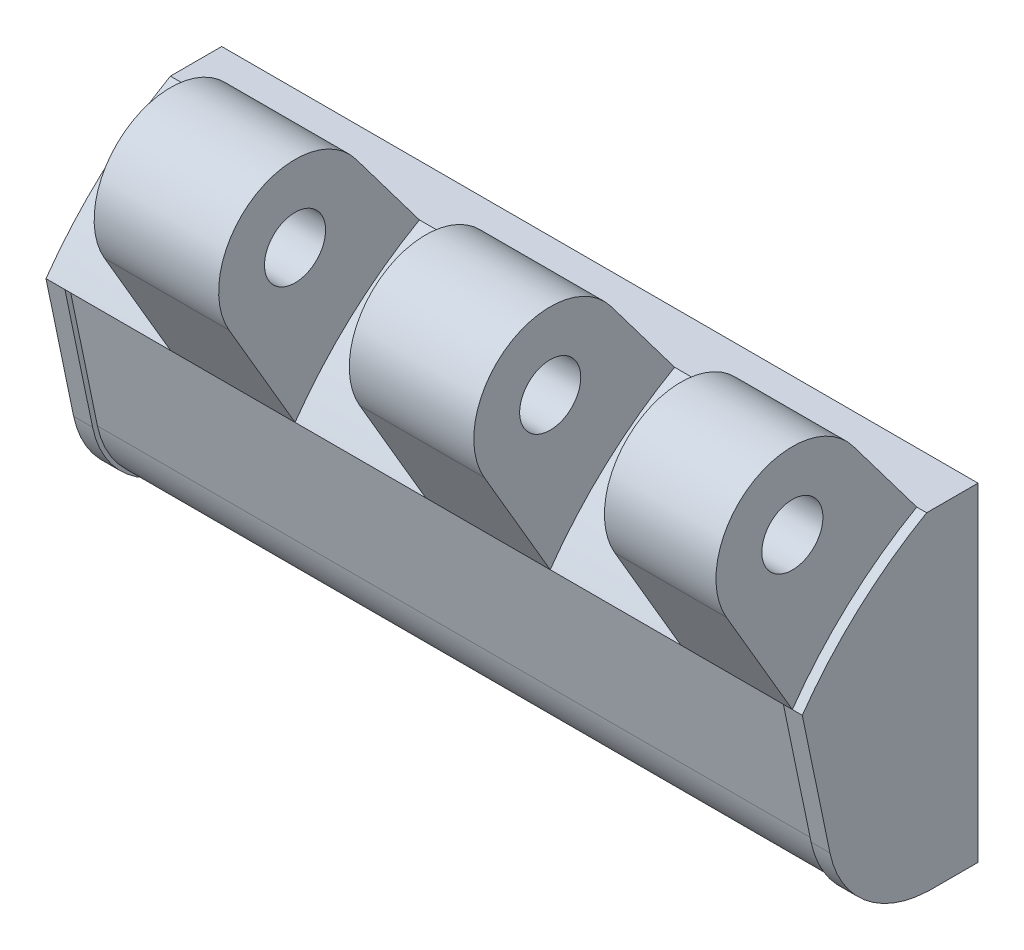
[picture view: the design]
ISO-10303-21;
HEADER;
FILE_DESCRIPTION(('STEP AP214'),'2;1');
FILE_NAME('part.step','',(''),(''),'','','');
FILE_SCHEMA(('AUTOMOTIVE_DESIGN { 1 0 10303 214 1 1 1 1 }'));
ENDSEC;
DATA;
#1=APPLICATION_CONTEXT('core data for automotive mechanical design processes');
#2=APPLICATION_PROTOCOL_DEFINITION('international standard','automotive_design',2000,#1);
#3=PRODUCT_CONTEXT('',#1,'mechanical');
#4=PRODUCT('Part','Part','',(#3));
#5=PRODUCT_RELATED_PRODUCT_CATEGORY('part','',(#4));
#6=PRODUCT_DEFINITION_FORMATION('','',#4);
#7=PRODUCT_DEFINITION_CONTEXT('part definition',#1,'design');
#8=PRODUCT_DEFINITION('design','',#6,#7);
#9=PRODUCT_DEFINITION_SHAPE('','',#8);
#10=(LENGTH_UNIT() NAMED_UNIT(*) SI_UNIT(.MILLI.,.METRE.));
#11=(NAMED_UNIT(*) PLANE_ANGLE_UNIT() SI_UNIT($,.RADIAN.));
#12=(NAMED_UNIT(*) SI_UNIT($,.STERADIAN.) SOLID_ANGLE_UNIT());
#13=UNCERTAINTY_MEASURE_WITH_UNIT(LENGTH_MEASURE(1.E-05),#10,'distance_accuracy_value','');
#14=(GEOMETRIC_REPRESENTATION_CONTEXT(3) GLOBAL_UNCERTAINTY_ASSIGNED_CONTEXT((#13)) GLOBAL_UNIT_ASSIGNED_CONTEXT((#10,
#11,#12)) REPRESENTATION_CONTEXT('',''));
#15=CARTESIAN_POINT('',(0.,0.,0.));
#16=DIRECTION('',(0.,0.,1.));
#17=DIRECTION('',(1.,0.,0.));
#18=AXIS2_PLACEMENT_3D('',#15,#16,#17);
#19=CARTESIAN_POINT('',(38.63875,-1.75,3.09));
#20=DIRECTION('',(1.,0.,0.));
#21=DIRECTION('',(0.,1.,0.));
#22=AXIS2_PLACEMENT_3D('',#19,#20,#21);
#23=CYLINDRICAL_SURFACE('',#22,5.54);
#24=DIRECTION('',(1.,0.,0.));
#25=VECTOR('',#24,1.);
#26=CARTESIAN_POINT('',(2.8867513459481,-5.,7.57654655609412));
#27=LINE('',#26,#25);
#28=CARTESIAN_POINT('',(2.8867513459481,-5.,7.57654655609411));
#29=VERTEX_POINT('',#28);
#30=CARTESIAN_POINT('',(-2.8867513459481,-5.,7.57654655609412));
#31=VERTEX_POINT('',#30);
#32=EDGE_CURVE('E448',#29,#31,#27,.F.);
#33=ORIENTED_EDGE('',*,*,#32,.T.);
#34=CARTESIAN_POINT('',(-4.7631397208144,-1.75,3.09));
#35=DIRECTION('',(-0.866025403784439,-0.5,0.));
#36=DIRECTION('',(0.5,-0.866025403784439,0.));
#37=AXIS2_PLACEMENT_3D('',#34,#35,#36);
#38=ELLIPSE('',#37,6.39704098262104,5.54);
#39=CARTESIAN_POINT('',(-4.11231595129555,-2.8772598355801,8.51410225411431));
#40=VERTEX_POINT('',#39);
#41=EDGE_CURVE('E386',#31,#40,#38,.T.);
#42=ORIENTED_EDGE('',*,*,#41,.T.);
#43=DIRECTION('',(1.,0.,0.));
#44=VECTOR('',#43,1.);
#45=CARTESIAN_POINT('',(38.63875,-2.8772598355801,8.51410225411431));
#46=LINE('',#45,#44);
#47=CARTESIAN_POINT('',(4.11231595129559,-2.8772598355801,8.51410225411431));
#48=VERTEX_POINT('',#47);
#49=EDGE_CURVE('E376',#48,#40,#46,.F.);
#50=ORIENTED_EDGE('',*,*,#49,.F.);
#51=CARTESIAN_POINT('',(4.7631397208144,-1.75,3.09));
#52=DIRECTION('',(0.866025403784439,-0.5,0.));
#53=DIRECTION('',(0.5,0.866025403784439,0.));
#54=AXIS2_PLACEMENT_3D('',#51,#52,#53);
#55=ELLIPSE('',#54,6.39704098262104,5.54);
#56=EDGE_CURVE('E450',#48,#29,#55,.T.);
#57=ORIENTED_EDGE('',*,*,#56,.T.);
#58=EDGE_LOOP('',(#33,#42,#50,#57));
#59=FACE_BOUND('',#58,.T.);
#60=ADVANCED_FACE('F14',(#59),#23,.F.);
#61=CARTESIAN_POINT('',(38.63875,-2.8772598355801,8.51410225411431));
#62=DIRECTION('',(0.,0.203476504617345,-0.979079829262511));
#63=DIRECTION('',(0.,0.979079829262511,0.203476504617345));
#64=AXIS2_PLACEMENT_3D('',#61,#62,#63);
#65=PLANE('',#64);
#66=DIRECTION('',(-1.,0.,0.));
#67=VECTOR('',#66,1.);
#68=CARTESIAN_POINT('',(-2.8867513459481,5.,10.151187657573));
#69=LINE('',#68,#67);
#70=CARTESIAN_POINT('',(-2.88675134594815,5.,10.151187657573));
#71=VERTEX_POINT('',#70);
#72=CARTESIAN_POINT('',(2.8867513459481,5.,10.151187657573));
#73=VERTEX_POINT('',#72);
#74=EDGE_CURVE('E476',#71,#73,#69,.F.);
#75=ORIENTED_EDGE('',*,*,#74,.T.);
#76=DIRECTION('',(0.492093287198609,-0.852330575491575,-0.177134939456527));
#77=VECTOR('',#76,1.);
#78=CARTESIAN_POINT('',(2.8867513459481,5.,10.151187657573));
#79=LINE('',#78,#77);
#80=CARTESIAN_POINT('',(5.77350269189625,0.,9.11206654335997));
#81=VERTEX_POINT('',#80);
#82=EDGE_CURVE('E495',#73,#81,#79,.T.);
#83=ORIENTED_EDGE('',*,*,#82,.T.);
#84=DIRECTION('',(-0.49209328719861,-0.852330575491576,-0.177134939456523));
#85=VECTOR('',#84,1.);
#86=CARTESIAN_POINT('',(5.77350269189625,0.,9.11206654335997));
#87=LINE('',#86,#85);
#88=EDGE_CURVE('E508',#81,#48,#87,.T.);
#89=ORIENTED_EDGE('',*,*,#88,.T.);
#90=ORIENTED_EDGE('',*,*,#49,.T.);
#91=DIRECTION('',(-0.49209328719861,0.852330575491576,0.177134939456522));
#92=VECTOR('',#91,1.);
#93=CARTESIAN_POINT('',(-4.11231595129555,-2.87725983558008,8.51410225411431));
#94=LINE('',#93,#92);
#95=CARTESIAN_POINT('',(-5.77350269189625,0.,9.11206654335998));
#96=VERTEX_POINT('',#95);
#97=EDGE_CURVE('E466',#40,#96,#94,.T.);
#98=ORIENTED_EDGE('',*,*,#97,.T.);
#99=DIRECTION('',(0.492093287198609,0.852330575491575,0.177134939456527));
#100=VECTOR('',#99,1.);
#101=CARTESIAN_POINT('',(-5.7735026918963,0.,9.11206654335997));
#102=LINE('',#101,#100);
#103=EDGE_CURVE('E463',#96,#71,#102,.T.);
#104=ORIENTED_EDGE('',*,*,#103,.T.);
#105=EDGE_LOOP('',(#75,#83,#89,#90,#98,#104));
#106=FACE_BOUND('',#105,.T.);
#107=ADVANCED_FACE('F16',(#106),#65,.T.);
#108=CARTESIAN_POINT('',(38.63875,-1.75,3.09));
#109=DIRECTION('',(1.,0.,0.));
#110=DIRECTION('',(0.,1.,0.));
#111=AXIS2_PLACEMENT_3D('',#108,#109,#110);
#112=CYLINDRICAL_SURFACE('',#111,5.54);
#113=DIRECTION('',(1.,0.,0.));
#114=VECTOR('',#113,1.);
#115=CARTESIAN_POINT('',(38.63875,-2.8772598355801,8.51410225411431));
#116=LINE('',#115,#114);
#117=CARTESIAN_POINT('',(34.6123159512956,-2.8772598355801,8.51410225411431));
#118=VERTEX_POINT('',#117);
#119=CARTESIAN_POINT('',(26.3876840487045,-2.8772598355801,8.51410225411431));
#120=VERTEX_POINT('',#119);
#121=EDGE_CURVE('E373',#118,#120,#116,.F.);
#122=ORIENTED_EDGE('',*,*,#121,.F.);
#123=CARTESIAN_POINT('',(35.2631397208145,-1.75,3.09));
#124=DIRECTION('',(0.866025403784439,-0.5,0.));
#125=DIRECTION('',(0.5,0.866025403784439,0.));
#126=AXIS2_PLACEMENT_3D('',#123,#124,#125);
#127=ELLIPSE('',#126,6.39704098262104,5.54);
#128=CARTESIAN_POINT('',(33.3867513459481,-5.,7.57654655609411));
#129=VERTEX_POINT('',#128);
#130=EDGE_CURVE('E385',#118,#129,#127,.T.);
#131=ORIENTED_EDGE('',*,*,#130,.T.);
#132=DIRECTION('',(1.,0.,0.));
#133=VECTOR('',#132,1.);
#134=CARTESIAN_POINT('',(33.3867513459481,-5.,7.57654655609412));
#135=LINE('',#134,#133);
#136=CARTESIAN_POINT('',(27.6132486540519,-5.,7.57654655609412));
#137=VERTEX_POINT('',#136);
#138=EDGE_CURVE('E383',#129,#137,#135,.F.);
#139=ORIENTED_EDGE('',*,*,#138,.T.);
#140=CARTESIAN_POINT('',(25.7368602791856,-1.75,3.09));
#141=DIRECTION('',(-0.866025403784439,-0.5,0.));
#142=DIRECTION('',(0.5,-0.866025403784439,0.));
#143=AXIS2_PLACEMENT_3D('',#140,#141,#142);
#144=ELLIPSE('',#143,6.39704098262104,5.54);
#145=EDGE_CURVE('E620',#137,#120,#144,.T.);
#146=ORIENTED_EDGE('',*,*,#145,.T.);
#147=EDGE_LOOP('',(#122,#131,#139,#146));
#148=FACE_BOUND('',#147,.T.);
#149=ADVANCED_FACE('F924',(#148),#112,.F.);
#150=CARTESIAN_POINT('',(38.63875,-2.8772598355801,8.51410225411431));
#151=DIRECTION('',(0.,0.203476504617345,-0.979079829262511));
#152=DIRECTION('',(0.,0.979079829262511,0.203476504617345));
#153=AXIS2_PLACEMENT_3D('',#150,#151,#152);
#154=PLANE('',#153);
#155=DIRECTION('',(-0.49209328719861,-0.852330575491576,-0.177134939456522));
#156=VECTOR('',#155,1.);
#157=CARTESIAN_POINT('',(36.2735026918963,0.,9.11206654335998));
#158=LINE('',#157,#156);
#159=CARTESIAN_POINT('',(36.2735026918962,0.,9.11206654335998));
#160=VERTEX_POINT('',#159);
#161=EDGE_CURVE('E439',#160,#118,#158,.T.);
#162=ORIENTED_EDGE('',*,*,#161,.T.);
#163=ORIENTED_EDGE('',*,*,#121,.T.);
#164=DIRECTION('',(-0.49209328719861,0.852330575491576,0.177134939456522));
#165=VECTOR('',#164,1.);
#166=CARTESIAN_POINT('',(26.3876840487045,-2.87725983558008,8.51410225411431));
#167=LINE('',#166,#165);
#168=CARTESIAN_POINT('',(24.7264973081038,0.,9.11206654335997));
#169=VERTEX_POINT('',#168);
#170=EDGE_CURVE('E622',#120,#169,#167,.T.);
#171=ORIENTED_EDGE('',*,*,#170,.T.);
#172=DIRECTION('',(0.492093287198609,0.852330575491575,0.177134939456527));
#173=VECTOR('',#172,1.);
#174=CARTESIAN_POINT('',(24.7264973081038,0.,9.11206654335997));
#175=LINE('',#174,#173);
#176=CARTESIAN_POINT('',(27.6132486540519,5.,10.151187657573));
#177=VERTEX_POINT('',#176);
#178=EDGE_CURVE('E380',#169,#177,#175,.T.);
#179=ORIENTED_EDGE('',*,*,#178,.T.);
#180=DIRECTION('',(-1.,0.,0.));
#181=VECTOR('',#180,1.);
#182=CARTESIAN_POINT('',(27.6132486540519,5.,10.151187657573));
#183=LINE('',#182,#181);
#184=CARTESIAN_POINT('',(33.3867513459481,5.,10.151187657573));
#185=VERTEX_POINT('',#184);
#186=EDGE_CURVE('E412',#177,#185,#183,.F.);
#187=ORIENTED_EDGE('',*,*,#186,.T.);
#188=DIRECTION('',(0.492093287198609,-0.852330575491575,-0.177134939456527));
#189=VECTOR('',#188,1.);
#190=CARTESIAN_POINT('',(33.3867513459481,5.,10.151187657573));
#191=LINE('',#190,#189);
#192=EDGE_CURVE('E426',#185,#160,#191,.T.);
#193=ORIENTED_EDGE('',*,*,#192,.T.);
#194=EDGE_LOOP('',(#162,#163,#171,#179,#187,#193));
#195=FACE_BOUND('',#194,.T.);
#196=ADVANCED_FACE('F748',(#195),#154,.T.);
#197=CARTESIAN_POINT('',(-2.8867513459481,5.,2.2));
#198=DIRECTION('',(0.,1.,0.));
#199=DIRECTION('',(-1.,0.,0.));
#200=AXIS2_PLACEMENT_3D('',#197,#198,#199);
#201=PLANE('',#200);
#202=DIRECTION('',(0.,0.,1.));
#203=VECTOR('',#202,1.);
#204=CARTESIAN_POINT('',(-2.88675134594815,5.,2.2));
#205=LINE('',#204,#203);
#206=CARTESIAN_POINT('',(-2.88675134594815,5.,2.2));
#207=VERTEX_POINT('',#206);
#208=EDGE_CURVE('E467',#71,#207,#205,.F.);
#209=ORIENTED_EDGE('',*,*,#208,.T.);
#210=DIRECTION('',(1.,0.,0.));
#211=VECTOR('',#210,1.);
#212=CARTESIAN_POINT('',(15.25,5.,2.2));
#213=LINE('',#212,#211);
#214=CARTESIAN_POINT('',(2.8867513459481,5.,2.2));
#215=VERTEX_POINT('',#214);
#216=EDGE_CURVE('E486',#215,#207,#213,.F.);
#217=ORIENTED_EDGE('',*,*,#216,.F.);
#218=DIRECTION('',(0.,0.,1.));
#219=VECTOR('',#218,1.);
#220=CARTESIAN_POINT('',(2.8867513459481,5.,2.2));
#221=LINE('',#220,#219);
#222=EDGE_CURVE('E481',#73,#215,#221,.F.);
#223=ORIENTED_EDGE('',*,*,#222,.F.);
#224=ORIENTED_EDGE('',*,*,#74,.F.);
#225=EDGE_LOOP('',(#209,#217,#223,#224));
#226=FACE_BOUND('',#225,.T.);
#227=ADVANCED_FACE('F726',(#226),#201,.F.);
#228=CARTESIAN_POINT('',(2.8867513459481,5.,2.2));
#229=DIRECTION('',(0.866025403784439,0.5,0.));
#230=DIRECTION('',(-0.5,0.866025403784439,0.));
#231=AXIS2_PLACEMENT_3D('',#228,#229,#230);
#232=PLANE('',#231);
#233=ORIENTED_EDGE('',*,*,#222,.T.);
#234=DIRECTION('',(-0.5,0.866025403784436,0.));
#235=VECTOR('',#234,1.);
#236=CARTESIAN_POINT('',(5.77350269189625,0.,2.2));
#237=LINE('',#236,#235);
#238=CARTESIAN_POINT('',(5.77350269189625,0.,2.2));
#239=VERTEX_POINT('',#238);
#240=EDGE_CURVE('E491',#239,#215,#237,.T.);
#241=ORIENTED_EDGE('',*,*,#240,.F.);
#242=DIRECTION('',(0.,0.,1.));
#243=VECTOR('',#242,1.);
#244=CARTESIAN_POINT('',(5.77350269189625,0.,2.2));
#245=LINE('',#244,#243);
#246=EDGE_CURVE('E500',#81,#239,#245,.F.);
#247=ORIENTED_EDGE('',*,*,#246,.F.);
#248=ORIENTED_EDGE('',*,*,#82,.F.);
#249=EDGE_LOOP('',(#233,#241,#247,#248));
#250=FACE_BOUND('',#249,.T.);
#251=ADVANCED_FACE('F723',(#250),#232,.F.);
#252=CARTESIAN_POINT('',(5.77350269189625,0.,2.2));
#253=DIRECTION('',(0.866025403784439,-0.5,0.));
#254=DIRECTION('',(0.5,0.866025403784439,0.));
#255=AXIS2_PLACEMENT_3D('',#252,#253,#254);
#256=PLANE('',#255);
#257=ORIENTED_EDGE('',*,*,#246,.T.);
#258=DIRECTION('',(0.5,0.866025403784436,0.));
#259=VECTOR('',#258,1.);
#260=CARTESIAN_POINT('',(2.8867513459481,-5.,2.2));
#261=LINE('',#260,#259);
#262=CARTESIAN_POINT('',(2.8867513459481,-5.,2.2));
#263=VERTEX_POINT('',#262);
#264=EDGE_CURVE('E454',#263,#239,#261,.T.);
#265=ORIENTED_EDGE('',*,*,#264,.F.);
#266=DIRECTION('',(0.,0.,1.));
#267=VECTOR('',#266,1.);
#268=CARTESIAN_POINT('',(2.8867513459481,-5.,2.2));
#269=LINE('',#268,#267);
#270=EDGE_CURVE('E627',#29,#263,#269,.F.);
#271=ORIENTED_EDGE('',*,*,#270,.F.);
#272=ORIENTED_EDGE('',*,*,#56,.F.);
#273=ORIENTED_EDGE('',*,*,#88,.F.);
#274=EDGE_LOOP('',(#257,#265,#271,#272,#273));
#275=FACE_BOUND('',#274,.T.);
#276=ADVANCED_FACE('F706',(#275),#256,.F.);
#277=CARTESIAN_POINT('',(2.8867513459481,-5.,2.2));
#278=DIRECTION('',(0.,-1.,0.));
#279=DIRECTION('',(1.,0.,0.));
#280=AXIS2_PLACEMENT_3D('',#277,#278,#279);
#281=PLANE('',#280);
#282=ORIENTED_EDGE('',*,*,#270,.T.);
#283=DIRECTION('',(1.,0.,0.));
#284=VECTOR('',#283,1.);
#285=CARTESIAN_POINT('',(15.25,-5.,2.2));
#286=LINE('',#285,#284);
#287=CARTESIAN_POINT('',(-2.8867513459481,-5.,2.2));
#288=VERTEX_POINT('',#287);
#289=EDGE_CURVE('E451',#288,#263,#286,.T.);
#290=ORIENTED_EDGE('',*,*,#289,.F.);
#291=DIRECTION('',(0.,0.,1.));
#292=VECTOR('',#291,1.);
#293=CARTESIAN_POINT('',(-2.8867513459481,-5.,2.2));
#294=LINE('',#293,#292);
#295=EDGE_CURVE('E472',#288,#31,#294,.T.);
#296=ORIENTED_EDGE('',*,*,#295,.T.);
#297=ORIENTED_EDGE('',*,*,#32,.F.);
#298=EDGE_LOOP('',(#282,#290,#296,#297));
#299=FACE_BOUND('',#298,.T.);
#300=ADVANCED_FACE('F702',(#299),#281,.F.);
#301=CARTESIAN_POINT('',(-2.8867513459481,-5.,2.2));
#302=DIRECTION('',(-0.866025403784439,-0.5,0.));
#303=DIRECTION('',(0.5,-0.866025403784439,0.));
#304=AXIS2_PLACEMENT_3D('',#301,#302,#303);
#305=PLANE('',#304);
#306=ORIENTED_EDGE('',*,*,#295,.F.);
#307=DIRECTION('',(0.500000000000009,-0.866025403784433,0.));
#308=VECTOR('',#307,1.);
#309=CARTESIAN_POINT('',(-5.7735026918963,0.,2.2));
#310=LINE('',#309,#308);
#311=CARTESIAN_POINT('',(-5.7735026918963,0.,2.2));
#312=VERTEX_POINT('',#311);
#313=EDGE_CURVE('E391',#312,#288,#310,.T.);
#314=ORIENTED_EDGE('',*,*,#313,.F.);
#315=DIRECTION('',(0.,0.,1.));
#316=VECTOR('',#315,1.);
#317=CARTESIAN_POINT('',(-5.77350269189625,0.,2.2));
#318=LINE('',#317,#316);
#319=EDGE_CURVE('E470',#96,#312,#318,.F.);
#320=ORIENTED_EDGE('',*,*,#319,.F.);
#321=ORIENTED_EDGE('',*,*,#97,.F.);
#322=ORIENTED_EDGE('',*,*,#41,.F.);
#323=EDGE_LOOP('',(#306,#314,#320,#321,#322));
#324=FACE_BOUND('',#323,.T.);
#325=ADVANCED_FACE('F716',(#324),#305,.F.);
#326=CARTESIAN_POINT('',(-5.7735026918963,0.,2.2));
#327=DIRECTION('',(-0.866025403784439,0.5,0.));
#328=DIRECTION('',(-0.5,-0.866025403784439,0.));
#329=AXIS2_PLACEMENT_3D('',#326,#327,#328);
#330=PLANE('',#329);
#331=ORIENTED_EDGE('',*,*,#319,.T.);
#332=DIRECTION('',(-0.500000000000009,-0.866025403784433,0.));
#333=VECTOR('',#332,1.);
#334=CARTESIAN_POINT('',(-2.8867513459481,5.,2.2));
#335=LINE('',#334,#333);
#336=EDGE_CURVE('E460',#207,#312,#335,.T.);
#337=ORIENTED_EDGE('',*,*,#336,.F.);
#338=ORIENTED_EDGE('',*,*,#208,.F.);
#339=ORIENTED_EDGE('',*,*,#103,.F.);
#340=EDGE_LOOP('',(#331,#337,#338,#339));
#341=FACE_BOUND('',#340,.T.);
#342=ADVANCED_FACE('F730',(#341),#330,.F.);
#343=CARTESIAN_POINT('',(27.6132486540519,5.,2.2));
#344=DIRECTION('',(0.,1.,0.));
#345=DIRECTION('',(-1.,0.,0.));
#346=AXIS2_PLACEMENT_3D('',#343,#344,#345);
#347=PLANE('',#346);
#348=DIRECTION('',(0.,0.,1.));
#349=VECTOR('',#348,1.);
#350=CARTESIAN_POINT('',(27.6132486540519,5.,2.2));
#351=LINE('',#350,#349);
#352=CARTESIAN_POINT('',(27.6132486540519,5.,2.2));
#353=VERTEX_POINT('',#352);
#354=EDGE_CURVE('E403',#177,#353,#351,.F.);
#355=ORIENTED_EDGE('',*,*,#354,.T.);
#356=DIRECTION('',(1.,0.,0.));
#357=VECTOR('',#356,1.);
#358=CARTESIAN_POINT('',(15.25,5.,2.2));
#359=LINE('',#358,#357);
#360=CARTESIAN_POINT('',(33.3867513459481,5.,2.2));
#361=VERTEX_POINT('',#360);
#362=EDGE_CURVE('E408',#361,#353,#359,.F.);
#363=ORIENTED_EDGE('',*,*,#362,.F.);
#364=DIRECTION('',(0.,0.,1.));
#365=VECTOR('',#364,1.);
#366=CARTESIAN_POINT('',(33.3867513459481,5.,2.2));
#367=LINE('',#366,#365);
#368=EDGE_CURVE('E417',#185,#361,#367,.F.);
#369=ORIENTED_EDGE('',*,*,#368,.F.);
#370=ORIENTED_EDGE('',*,*,#186,.F.);
#371=EDGE_LOOP('',(#355,#363,#369,#370));
#372=FACE_BOUND('',#371,.T.);
#373=ADVANCED_FACE('F732',(#372),#347,.F.);
#374=CARTESIAN_POINT('',(33.3867513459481,5.,2.2));
#375=DIRECTION('',(0.866025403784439,0.5,0.));
#376=DIRECTION('',(-0.5,0.866025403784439,0.));
#377=AXIS2_PLACEMENT_3D('',#374,#375,#376);
#378=PLANE('',#377);
#379=ORIENTED_EDGE('',*,*,#368,.T.);
#380=DIRECTION('',(-0.500000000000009,0.866025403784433,0.));
#381=VECTOR('',#380,1.);
#382=CARTESIAN_POINT('',(36.2735026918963,0.,2.2));
#383=LINE('',#382,#381);
#384=CARTESIAN_POINT('',(36.2735026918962,0.,2.2));
#385=VERTEX_POINT('',#384);
#386=EDGE_CURVE('E422',#385,#361,#383,.T.);
#387=ORIENTED_EDGE('',*,*,#386,.F.);
#388=DIRECTION('',(0.,0.,1.));
#389=VECTOR('',#388,1.);
#390=CARTESIAN_POINT('',(36.2735026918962,0.,2.2));
#391=LINE('',#390,#389);
#392=EDGE_CURVE('E431',#160,#385,#391,.F.);
#393=ORIENTED_EDGE('',*,*,#392,.F.);
#394=ORIENTED_EDGE('',*,*,#192,.F.);
#395=EDGE_LOOP('',(#379,#387,#393,#394));
#396=FACE_BOUND('',#395,.T.);
#397=ADVANCED_FACE('F740',(#396),#378,.F.);
#398=CARTESIAN_POINT('',(36.2735026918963,0.,2.2));
#399=DIRECTION('',(0.866025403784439,-0.5,0.));
#400=DIRECTION('',(0.5,0.866025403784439,0.));
#401=AXIS2_PLACEMENT_3D('',#398,#399,#400);
#402=PLANE('',#401);
#403=ORIENTED_EDGE('',*,*,#392,.T.);
#404=DIRECTION('',(0.500000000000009,0.866025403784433,0.));
#405=VECTOR('',#404,1.);
#406=CARTESIAN_POINT('',(33.3867513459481,-5.,2.2));
#407=LINE('',#406,#405);
#408=CARTESIAN_POINT('',(33.3867513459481,-5.,2.2));
#409=VERTEX_POINT('',#408);
#410=EDGE_CURVE('E390',#409,#385,#407,.T.);
#411=ORIENTED_EDGE('',*,*,#410,.F.);
#412=DIRECTION('',(0.,0.,1.));
#413=VECTOR('',#412,1.);
#414=CARTESIAN_POINT('',(33.3867513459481,-5.,2.2));
#415=LINE('',#414,#413);
#416=EDGE_CURVE('E624',#129,#409,#415,.F.);
#417=ORIENTED_EDGE('',*,*,#416,.F.);
#418=ORIENTED_EDGE('',*,*,#130,.F.);
#419=ORIENTED_EDGE('',*,*,#161,.F.);
#420=EDGE_LOOP('',(#403,#411,#417,#418,#419));
#421=FACE_BOUND('',#420,.T.);
#422=ADVANCED_FACE('F900',(#421),#402,.F.);
#423=CARTESIAN_POINT('',(33.3867513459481,-5.,2.2));
#424=DIRECTION('',(0.,-1.,0.));
#425=DIRECTION('',(1.,0.,0.));
#426=AXIS2_PLACEMENT_3D('',#423,#424,#425);
#427=PLANE('',#426);
#428=ORIENTED_EDGE('',*,*,#416,.T.);
#429=DIRECTION('',(1.,0.,0.));
#430=VECTOR('',#429,1.);
#431=CARTESIAN_POINT('',(15.25,-5.,2.2));
#432=LINE('',#431,#430);
#433=CARTESIAN_POINT('',(27.6132486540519,-5.,2.2));
#434=VERTEX_POINT('',#433);
#435=EDGE_CURVE('E387',#434,#409,#432,.T.);
#436=ORIENTED_EDGE('',*,*,#435,.F.);
#437=DIRECTION('',(0.,0.,1.));
#438=VECTOR('',#437,1.);
#439=CARTESIAN_POINT('',(27.6132486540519,-5.,2.2));
#440=LINE('',#439,#438);
#441=EDGE_CURVE('E379',#434,#137,#440,.T.);
#442=ORIENTED_EDGE('',*,*,#441,.T.);
#443=ORIENTED_EDGE('',*,*,#138,.F.);
#444=EDGE_LOOP('',(#428,#436,#442,#443));
#445=FACE_BOUND('',#444,.T.);
#446=ADVANCED_FACE('F745',(#445),#427,.F.);
#447=CARTESIAN_POINT('',(27.6132486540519,-5.,2.2));
#448=DIRECTION('',(-0.866025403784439,-0.5,0.));
#449=DIRECTION('',(0.5,-0.866025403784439,0.));
#450=AXIS2_PLACEMENT_3D('',#447,#448,#449);
#451=PLANE('',#450);
#452=ORIENTED_EDGE('',*,*,#145,.F.);
#453=ORIENTED_EDGE('',*,*,#441,.F.);
#454=DIRECTION('',(0.5,-0.866025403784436,0.));
#455=VECTOR('',#454,1.);
#456=CARTESIAN_POINT('',(24.7264973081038,0.,2.2));
#457=LINE('',#456,#455);
#458=CARTESIAN_POINT('',(24.7264973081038,0.,2.2));
#459=VERTEX_POINT('',#458);
#460=EDGE_CURVE('E394',#459,#434,#457,.T.);
#461=ORIENTED_EDGE('',*,*,#460,.F.);
#462=DIRECTION('',(0.,0.,1.));
#463=VECTOR('',#462,1.);
#464=CARTESIAN_POINT('',(24.7264973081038,0.,2.2));
#465=LINE('',#464,#463);
#466=EDGE_CURVE('E377',#169,#459,#465,.F.);
#467=ORIENTED_EDGE('',*,*,#466,.F.);
#468=ORIENTED_EDGE('',*,*,#170,.F.);
#469=EDGE_LOOP('',(#452,#453,#461,#467,#468));
#470=FACE_BOUND('',#469,.T.);
#471=ADVANCED_FACE('F891',(#470),#451,.F.);
#472=CARTESIAN_POINT('',(24.7264973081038,0.,2.2));
#473=DIRECTION('',(-0.866025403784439,0.5,0.));
#474=DIRECTION('',(-0.5,-0.866025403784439,0.));
#475=AXIS2_PLACEMENT_3D('',#472,#473,#474);
#476=PLANE('',#475);
#477=ORIENTED_EDGE('',*,*,#466,.T.);
#478=DIRECTION('',(-0.5,-0.866025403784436,0.));
#479=VECTOR('',#478,1.);
#480=CARTESIAN_POINT('',(27.6132486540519,5.,2.2));
#481=LINE('',#480,#479);
#482=EDGE_CURVE('E398',#353,#459,#481,.T.);
#483=ORIENTED_EDGE('',*,*,#482,.F.);
#484=ORIENTED_EDGE('',*,*,#354,.F.);
#485=ORIENTED_EDGE('',*,*,#178,.F.);
#486=EDGE_LOOP('',(#477,#483,#484,#485));
#487=FACE_BOUND('',#486,.T.);
#488=ADVANCED_FACE('F743',(#487),#476,.F.);
#489=CARTESIAN_POINT('',(15.25,15.5,2.2));
#490=DIRECTION('',(0.,0.,1.));
#491=DIRECTION('',(1.,0.,0.));
#492=AXIS2_PLACEMENT_3D('',#489,#490,#491);
#493=PLANE('',#492);
#494=ORIENTED_EDGE('',*,*,#336,.T.);
#495=ORIENTED_EDGE('',*,*,#313,.T.);
#496=ORIENTED_EDGE('',*,*,#289,.T.);
#497=ORIENTED_EDGE('',*,*,#264,.T.);
#498=ORIENTED_EDGE('',*,*,#240,.T.);
#499=ORIENTED_EDGE('',*,*,#216,.T.);
#500=EDGE_LOOP('',(#494,#495,#496,#497,#498,#499));
#501=FACE_BOUND('',#500,.T.);
#502=CARTESIAN_POINT('',(0.,0.,2.2));
#503=DIRECTION('',(0.,0.,1.));
#504=DIRECTION('',(1.,0.,0.));
#505=AXIS2_PLACEMENT_3D('',#502,#503,#504);
#506=CIRCLE('',#505,3.25);
#507=CARTESIAN_POINT('',(3.25,0.,2.2));
#508=VERTEX_POINT('',#507);
#509=EDGE_CURVE('E550',#508,#508,#506,.F.);
#510=ORIENTED_EDGE('',*,*,#509,.T.);
#511=EDGE_LOOP('',(#510));
#512=FACE_BOUND('',#511,.T.);
#513=ADVANCED_FACE('F710',(#501,#512),#493,.T.);
#514=CARTESIAN_POINT('',(15.25,15.5,2.2));
#515=DIRECTION('',(0.,0.,1.));
#516=DIRECTION('',(1.,0.,0.));
#517=AXIS2_PLACEMENT_3D('',#514,#515,#516);
#518=PLANE('',#517);
#519=ORIENTED_EDGE('',*,*,#482,.T.);
#520=ORIENTED_EDGE('',*,*,#460,.T.);
#521=ORIENTED_EDGE('',*,*,#435,.T.);
#522=ORIENTED_EDGE('',*,*,#410,.T.);
#523=ORIENTED_EDGE('',*,*,#386,.T.);
#524=ORIENTED_EDGE('',*,*,#362,.T.);
#525=EDGE_LOOP('',(#519,#520,#521,#522,#523,#524));
#526=FACE_BOUND('',#525,.T.);
#527=CARTESIAN_POINT('',(30.5,0.,2.2));
#528=DIRECTION('',(0.,0.,1.));
#529=DIRECTION('',(1.,0.,0.));
#530=AXIS2_PLACEMENT_3D('',#527,#528,#529);
#531=CIRCLE('',#530,3.25);
#532=CARTESIAN_POINT('',(33.75,0.,2.2));
#533=VERTEX_POINT('',#532);
#534=EDGE_CURVE('E547',#533,#533,#531,.F.);
#535=ORIENTED_EDGE('',*,*,#534,.T.);
#536=EDGE_LOOP('',(#535));
#537=FACE_BOUND('',#536,.T.);
#538=ADVANCED_FACE('F792',(#526,#537),#518,.T.);
#539=CARTESIAN_POINT('',(0.,0.,2.2));
#540=DIRECTION('',(0.,0.,1.));
#541=DIRECTION('',(1.,0.,0.));
#542=AXIS2_PLACEMENT_3D('',#539,#540,#541);
#543=CYLINDRICAL_SURFACE('',#542,3.25);
#544=ORIENTED_EDGE('',*,*,#509,.F.);
#545=EDGE_LOOP('',(#544));
#546=FACE_BOUND('',#545,.T.);
#547=CARTESIAN_POINT('',(0.,0.,0.));
#548=DIRECTION('',(0.,0.,1.));
#549=DIRECTION('',(1.,0.,0.));
#550=AXIS2_PLACEMENT_3D('',#547,#548,#549);
#551=CIRCLE('',#550,3.25);
#552=CARTESIAN_POINT('',(3.25,0.,0.));
#553=VERTEX_POINT('',#552);
#554=EDGE_CURVE('E527',#553,#553,#551,.T.);
#555=ORIENTED_EDGE('',*,*,#554,.F.);
#556=EDGE_LOOP('',(#555));
#557=FACE_BOUND('',#556,.T.);
#558=ADVANCED_FACE('F788',(#546,#557),#543,.F.);
#559=CARTESIAN_POINT('',(30.5,0.,2.2));
#560=DIRECTION('',(0.,0.,1.));
#561=DIRECTION('',(1.,0.,0.));
#562=AXIS2_PLACEMENT_3D('',#559,#560,#561);
#563=CYLINDRICAL_SURFACE('',#562,3.25);
#564=ORIENTED_EDGE('',*,*,#534,.F.);
#565=EDGE_LOOP('',(#564));
#566=FACE_BOUND('',#565,.T.);
#567=CARTESIAN_POINT('',(30.5,0.,0.));
#568=DIRECTION('',(0.,0.,1.));
#569=DIRECTION('',(1.,0.,0.));
#570=AXIS2_PLACEMENT_3D('',#567,#568,#569);
#571=CIRCLE('',#570,3.25);
#572=CARTESIAN_POINT('',(33.75,0.,0.));
#573=VERTEX_POINT('',#572);
#574=EDGE_CURVE('E523',#573,#573,#571,.T.);
#575=ORIENTED_EDGE('',*,*,#574,.F.);
#576=EDGE_LOOP('',(#575));
#577=FACE_BOUND('',#576,.T.);
#578=ADVANCED_FACE('F785',(#566,#577),#563,.F.);
#579=CARTESIAN_POINT('',(38.7625,-1.75,3.09));
#580=DIRECTION('',(1.,0.,0.));
#581=DIRECTION('',(0.,1.,0.));
#582=AXIS2_PLACEMENT_3D('',#579,#580,#581);
#583=CYLINDRICAL_SURFACE('',#582,5.54);
#584=CARTESIAN_POINT('',(-8.2625,-1.75,3.09));
#585=DIRECTION('',(1.,0.,0.));
#586=DIRECTION('',(0.,1.,0.));
#587=AXIS2_PLACEMENT_3D('',#584,#585,#586);
#588=CIRCLE('',#587,5.54);
#589=CARTESIAN_POINT('',(-8.2625,-7.28345498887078,3.35921345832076));
#590=VERTEX_POINT('',#589);
#591=CARTESIAN_POINT('',(-8.2625,-2.8772598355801,8.51410225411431));
#592=VERTEX_POINT('',#591);
#593=EDGE_CURVE('E617',#590,#592,#588,.F.);
#594=ORIENTED_EDGE('',*,*,#593,.F.);
#595=DIRECTION('',(1.,0.,0.));
#596=VECTOR('',#595,1.);
#597=CARTESIAN_POINT('',(38.7625,-7.28345498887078,3.35921345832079));
#598=LINE('',#597,#596);
#599=CARTESIAN_POINT('',(-8.13875,-7.28345498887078,3.35921345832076));
#600=VERTEX_POINT('',#599);
#601=EDGE_CURVE('E316',#590,#600,#598,.T.);
#602=ORIENTED_EDGE('',*,*,#601,.T.);
#603=CARTESIAN_POINT('',(-8.13875,-1.75,3.09));
#604=DIRECTION('',(1.,0.,0.));
#605=DIRECTION('',(0.,1.,0.));
#606=AXIS2_PLACEMENT_3D('',#603,#604,#605);
#607=CIRCLE('',#606,5.54);
#608=CARTESIAN_POINT('',(-8.13875,-2.8772598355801,8.51410225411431));
#609=VERTEX_POINT('',#608);
#610=EDGE_CURVE('E18',#600,#609,#607,.F.);
#611=ORIENTED_EDGE('',*,*,#610,.T.);
#612=DIRECTION('',(1.,0.,0.));
#613=VECTOR('',#612,1.);
#614=CARTESIAN_POINT('',(38.7625,-2.8772598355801,8.51410225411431));
#615=LINE('',#614,#613);
#616=EDGE_CURVE('E304',#609,#592,#615,.F.);
#617=ORIENTED_EDGE('',*,*,#616,.T.);
#618=EDGE_LOOP('',(#594,#602,#611,#617));
#619=FACE_BOUND('',#618,.T.);
#620=ADVANCED_FACE('F319',(#619),#583,.T.);
#621=CARTESIAN_POINT('',(38.7625,-1.75,3.09));
#622=DIRECTION('',(1.,0.,0.));
#623=DIRECTION('',(0.,1.,0.));
#624=AXIS2_PLACEMENT_3D('',#621,#622,#623);
#625=CYLINDRICAL_SURFACE('',#624,5.54);
#626=CARTESIAN_POINT('',(38.7625,-1.75,3.09));
#627=DIRECTION('',(1.,0.,0.));
#628=DIRECTION('',(0.,1.,0.));
#629=AXIS2_PLACEMENT_3D('',#626,#627,#628);
#630=CIRCLE('',#629,5.54);
#631=CARTESIAN_POINT('',(38.7625,-7.28345498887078,3.35921345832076));
#632=VERTEX_POINT('',#631);
#633=CARTESIAN_POINT('',(38.7625,-2.8772598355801,8.51410225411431));
#634=VERTEX_POINT('',#633);
#635=EDGE_CURVE('E596',#632,#634,#630,.F.);
#636=ORIENTED_EDGE('',*,*,#635,.T.);
#637=DIRECTION('',(1.,0.,0.));
#638=VECTOR('',#637,1.);
#639=CARTESIAN_POINT('',(38.7625,-2.8772598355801,8.51410225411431));
#640=LINE('',#639,#638);
#641=CARTESIAN_POINT('',(38.63875,-2.8772598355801,8.51410225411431));
#642=VERTEX_POINT('',#641);
#643=EDGE_CURVE('E325',#634,#642,#640,.F.);
#644=ORIENTED_EDGE('',*,*,#643,.T.);
#645=CARTESIAN_POINT('',(38.63875,-1.75,3.09));
#646=DIRECTION('',(1.,0.,0.));
#647=DIRECTION('',(0.,1.,0.));
#648=AXIS2_PLACEMENT_3D('',#645,#646,#647);
#649=CIRCLE('',#648,5.54);
#650=CARTESIAN_POINT('',(38.63875,-7.28345498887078,3.35921345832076));
#651=VERTEX_POINT('',#650);
#652=EDGE_CURVE('E628',#651,#642,#649,.F.);
#653=ORIENTED_EDGE('',*,*,#652,.F.);
#654=DIRECTION('',(1.,0.,0.));
#655=VECTOR('',#654,1.);
#656=CARTESIAN_POINT('',(38.7625,-7.28345498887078,3.35921345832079));
#657=LINE('',#656,#655);
#658=EDGE_CURVE('E328',#651,#632,#657,.T.);
#659=ORIENTED_EDGE('',*,*,#658,.T.);
#660=EDGE_LOOP('',(#636,#644,#653,#659));
#661=FACE_BOUND('',#660,.T.);
#662=ADVANCED_FACE('F841',(#661),#625,.T.);
#663=CARTESIAN_POINT('',(38.63875,-1.75,3.09));
#664=DIRECTION('',(1.,0.,0.));
#665=DIRECTION('',(0.,1.,0.));
#666=AXIS2_PLACEMENT_3D('',#663,#664,#665);
#667=CYLINDRICAL_SURFACE('',#666,6.54);
#668=CARTESIAN_POINT('',(38.63875,-1.75,3.09));
#669=DIRECTION('',(1.,0.,0.));
#670=DIRECTION('',(0.,1.,0.));
#671=AXIS2_PLACEMENT_3D('',#668,#669,#670);
#672=CIRCLE('',#671,6.54);
#673=CARTESIAN_POINT('',(38.63875,-8.28445668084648,3.35921345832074));
#674=VERTEX_POINT('',#673);
#675=CARTESIAN_POINT('',(38.63875,-3.08073634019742,9.49318208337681));
#676=VERTEX_POINT('',#675);
#677=EDGE_CURVE('E589',#674,#676,#672,.F.);
#678=ORIENTED_EDGE('',*,*,#677,.T.);
#679=DIRECTION('',(1.,0.,0.));
#680=VECTOR('',#679,1.);
#681=CARTESIAN_POINT('',(38.63875,-3.08073634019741,9.49318208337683));
#682=LINE('',#681,#680);
#683=CARTESIAN_POINT('',(-8.13875,-3.08073634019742,9.49318208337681));
#684=VERTEX_POINT('',#683);
#685=EDGE_CURVE('E455',#676,#684,#682,.F.);
#686=ORIENTED_EDGE('',*,*,#685,.T.);
#687=CARTESIAN_POINT('',(-8.13875,-1.75,3.09));
#688=DIRECTION('',(1.,0.,0.));
#689=DIRECTION('',(0.,1.,0.));
#690=AXIS2_PLACEMENT_3D('',#687,#688,#689);
#691=CIRCLE('',#690,6.54);
#692=CARTESIAN_POINT('',(-8.13875,-8.28445668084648,3.35921345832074));
#693=VERTEX_POINT('',#692);
#694=EDGE_CURVE('E592',#684,#693,#691,.T.);
#695=ORIENTED_EDGE('',*,*,#694,.T.);
#696=DIRECTION('',(1.,0.,0.));
#697=VECTOR('',#696,1.);
#698=CARTESIAN_POINT('',(40.,-8.2844566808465,3.35921345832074));
#699=LINE('',#698,#697);
#700=EDGE_CURVE('E553',#674,#693,#699,.F.);
#701=ORIENTED_EDGE('',*,*,#700,.F.);
#702=EDGE_LOOP('',(#678,#686,#695,#701));
#703=FACE_BOUND('',#702,.T.);
#704=ADVANCED_FACE('F764',(#703),#667,.T.);
#705=CARTESIAN_POINT('',(40.,-1.75,3.09));
#706=DIRECTION('',(1.,0.,0.));
#707=DIRECTION('',(0.,1.,0.));
#708=AXIS2_PLACEMENT_3D('',#705,#706,#707);
#709=CYLINDRICAL_SURFACE('',#708,6.74);
#710=CARTESIAN_POINT('',(-9.5,-1.75,3.09));
#711=DIRECTION('',(1.,0.,0.));
#712=DIRECTION('',(0.,1.,0.));
#713=AXIS2_PLACEMENT_3D('',#710,#711,#712);
#714=CIRCLE('',#713,6.74);
#715=CARTESIAN_POINT('',(-9.5,-3.12143164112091,9.68899804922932));
#716=VERTEX_POINT('',#715);
#717=CARTESIAN_POINT('',(-9.5,-8.48462130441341,3.35921345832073));
#718=VERTEX_POINT('',#717);
#719=EDGE_CURVE('E540',#716,#718,#714,.T.);
#720=ORIENTED_EDGE('',*,*,#719,.T.);
#721=DIRECTION('',(1.,0.,0.));
#722=VECTOR('',#721,1.);
#723=CARTESIAN_POINT('',(40.,-8.4846213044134,3.35921345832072));
#724=LINE('',#723,#722);
#725=CARTESIAN_POINT('',(-8.2625,-8.48462130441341,3.35921345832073));
#726=VERTEX_POINT('',#725);
#727=EDGE_CURVE('E1384',#726,#718,#724,.F.);
#728=ORIENTED_EDGE('',*,*,#727,.F.);
#729=CARTESIAN_POINT('',(-8.2625,-1.75,3.09));
#730=DIRECTION('',(1.,0.,0.));
#731=DIRECTION('',(0.,1.,0.));
#732=AXIS2_PLACEMENT_3D('',#729,#730,#731);
#733=CIRCLE('',#732,6.74);
#734=CARTESIAN_POINT('',(-8.2625,-3.12143164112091,9.68899804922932));
#735=VERTEX_POINT('',#734);
#736=EDGE_CURVE('E586',#726,#735,#733,.F.);
#737=ORIENTED_EDGE('',*,*,#736,.T.);
#738=DIRECTION('',(1.,0.,0.));
#739=VECTOR('',#738,1.);
#740=CARTESIAN_POINT('',(40.,-3.1214316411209,9.68899804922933));
#741=LINE('',#740,#739);
#742=EDGE_CURVE('E585',#735,#716,#741,.F.);
#743=ORIENTED_EDGE('',*,*,#742,.T.);
#744=EDGE_LOOP('',(#720,#728,#737,#743));
#745=FACE_BOUND('',#744,.T.);
#746=ADVANCED_FACE('F752',(#745),#709,.T.);
#747=CARTESIAN_POINT('',(40.,-8.5,0.));
#748=DIRECTION('',(0.,0.,-1.));
#749=DIRECTION('',(-1.,0.,0.));
#750=AXIS2_PLACEMENT_3D('',#747,#748,#749);
#751=PLANE('',#750);
#752=DIRECTION('',(0.,1.,0.));
#753=VECTOR('',#752,1.);
#754=CARTESIAN_POINT('',(40.,-8.5,0.));
#755=LINE('',#754,#753);
#756=CARTESIAN_POINT('',(40.,13.,0.));
#757=VERTEX_POINT('',#756);
#758=CARTESIAN_POINT('',(40.,-8.5,0.));
#759=VERTEX_POINT('',#758);
#760=EDGE_CURVE('E24',#757,#759,#755,.F.);
#761=ORIENTED_EDGE('',*,*,#760,.T.);
#762=DIRECTION('',(-1.,0.,0.));
#763=VECTOR('',#762,1.);
#764=CARTESIAN_POINT('',(40.,-8.5,0.));
#765=LINE('',#764,#763);
#766=CARTESIAN_POINT('',(-9.5,-8.5,0.));
#767=VERTEX_POINT('',#766);
#768=EDGE_CURVE('E9',#759,#767,#765,.T.);
#769=ORIENTED_EDGE('',*,*,#768,.T.);
#770=DIRECTION('',(0.,1.,0.));
#771=VECTOR('',#770,1.);
#772=CARTESIAN_POINT('',(-9.5,-8.5,0.));
#773=LINE('',#772,#771);
#774=CARTESIAN_POINT('',(-9.5,13.,0.));
#775=VERTEX_POINT('',#774);
#776=EDGE_CURVE('E526',#767,#775,#773,.T.);
#777=ORIENTED_EDGE('',*,*,#776,.T.);
#778=DIRECTION('',(-1.,0.,0.));
#779=VECTOR('',#778,1.);
#780=CARTESIAN_POINT('',(40.,13.,0.));
#781=LINE('',#780,#779);
#782=EDGE_CURVE('E1399',#775,#757,#781,.F.);
#783=ORIENTED_EDGE('',*,*,#782,.T.);
#784=EDGE_LOOP('',(#761,#769,#777,#783));
#785=FACE_BOUND('',#784,.T.);
#786=ORIENTED_EDGE('',*,*,#574,.T.);
#787=EDGE_LOOP('',(#786));
#788=FACE_BOUND('',#787,.T.);
#789=ORIENTED_EDGE('',*,*,#554,.T.);
#790=EDGE_LOOP('',(#789));
#791=FACE_BOUND('',#790,.T.);
#792=ADVANCED_FACE('F749',(#785,#788,#791),#751,.T.);
#793=CARTESIAN_POINT('',(40.,-8.5,3.35921345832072));
#794=DIRECTION('',(0.,-1.,0.));
#795=DIRECTION('',(1.,0.,0.));
#796=AXIS2_PLACEMENT_3D('',#793,#794,#795);
#797=PLANE('',#796);
#798=DIRECTION('',(0.,0.,1.));
#799=VECTOR('',#798,1.);
#800=CARTESIAN_POINT('',(40.,-8.5,3.35921345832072));
#801=LINE('',#800,#799);
#802=CARTESIAN_POINT('',(40.,-8.5,3.35921345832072));
#803=VERTEX_POINT('',#802);
#804=EDGE_CURVE('E33',#759,#803,#801,.T.);
#805=ORIENTED_EDGE('',*,*,#804,.T.);
#806=DIRECTION('',(1.,0.,0.));
#807=VECTOR('',#806,1.);
#808=CARTESIAN_POINT('',(40.,-8.5,3.35921345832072));
#809=LINE('',#808,#807);
#810=CARTESIAN_POINT('',(-9.5,-8.5,3.35921345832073));
#811=VERTEX_POINT('',#810);
#812=EDGE_CURVE('E530',#803,#811,#809,.F.);
#813=ORIENTED_EDGE('',*,*,#812,.T.);
#814=DIRECTION('',(0.,0.,1.));
#815=VECTOR('',#814,1.);
#816=CARTESIAN_POINT('',(-9.5,-8.5,3.35921345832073));
#817=LINE('',#816,#815);
#818=EDGE_CURVE('E1367',#811,#767,#817,.F.);
#819=ORIENTED_EDGE('',*,*,#818,.T.);
#820=ORIENTED_EDGE('',*,*,#768,.F.);
#821=EDGE_LOOP('',(#805,#813,#819,#820));
#822=FACE_BOUND('',#821,.T.);
#823=ADVANCED_FACE('F751',(#822),#797,.T.);
#824=CARTESIAN_POINT('',(40.,-8.4846213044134,3.35921345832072));
#825=DIRECTION('',(0.,0.,1.));
#826=DIRECTION('',(0.,-1.,0.));
#827=AXIS2_PLACEMENT_3D('',#824,#825,#826);
#828=PLANE('',#827);
#829=DIRECTION('',(0.,1.,0.));
#830=VECTOR('',#829,1.);
#831=CARTESIAN_POINT('',(38.63875,15.5,3.35921345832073));
#832=LINE('',#831,#830);
#833=EDGE_CURVE('E321',#674,#651,#832,.T.);
#834=ORIENTED_EDGE('',*,*,#833,.F.);
#835=ORIENTED_EDGE('',*,*,#700,.T.);
#836=DIRECTION('',(0.,1.,0.));
#837=VECTOR('',#836,1.);
#838=CARTESIAN_POINT('',(-8.13875,15.5,3.35921345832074));
#839=LINE('',#838,#837);
#840=EDGE_CURVE('E298',#693,#600,#839,.T.);
#841=ORIENTED_EDGE('',*,*,#840,.T.);
#842=ORIENTED_EDGE('',*,*,#601,.F.);
#843=DIRECTION('',(0.,1.,0.));
#844=VECTOR('',#843,1.);
#845=CARTESIAN_POINT('',(-8.2625,15.5,3.35921345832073));
#846=LINE('',#845,#844);
#847=EDGE_CURVE('E619',#726,#590,#846,.T.);
#848=ORIENTED_EDGE('',*,*,#847,.F.);
#849=ORIENTED_EDGE('',*,*,#727,.T.);
#850=DIRECTION('',(0.,1.,0.));
#851=VECTOR('',#850,1.);
#852=CARTESIAN_POINT('',(-9.5,15.5,3.35921345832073));
#853=LINE('',#852,#851);
#854=EDGE_CURVE('E542',#718,#811,#853,.F.);
#855=ORIENTED_EDGE('',*,*,#854,.T.);
#856=ORIENTED_EDGE('',*,*,#812,.F.);
#857=DIRECTION('',(0.,1.,0.));
#858=VECTOR('',#857,1.);
#859=CARTESIAN_POINT('',(40.,15.5,3.35921345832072));
#860=LINE('',#859,#858);
#861=CARTESIAN_POINT('',(40.,-8.48462130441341,3.35921345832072));
#862=VERTEX_POINT('',#861);
#863=EDGE_CURVE('E534',#862,#803,#860,.F.);
#864=ORIENTED_EDGE('',*,*,#863,.F.);
#865=DIRECTION('',(1.,0.,0.));
#866=VECTOR('',#865,1.);
#867=CARTESIAN_POINT('',(40.,-8.4846213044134,3.35921345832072));
#868=LINE('',#867,#866);
#869=CARTESIAN_POINT('',(38.7625,-8.48462130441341,3.35921345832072));
#870=VERTEX_POINT('',#869);
#871=EDGE_CURVE('E641',#862,#870,#868,.F.);
#872=ORIENTED_EDGE('',*,*,#871,.T.);
#873=DIRECTION('',(0.,1.,0.));
#874=VECTOR('',#873,1.);
#875=CARTESIAN_POINT('',(38.7625,15.5,3.35921345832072));
#876=LINE('',#875,#874);
#877=EDGE_CURVE('E599',#870,#632,#876,.T.);
#878=ORIENTED_EDGE('',*,*,#877,.T.);
#879=ORIENTED_EDGE('',*,*,#658,.F.);
#880=EDGE_LOOP('',(#834,#835,#841,#842,#848,#849,#855,#856,#864,#872,#878,#879));
#881=FACE_BOUND('',#880,.T.);
#882=ADVANCED_FACE('F760',(#881),#828,.T.);
#883=CARTESIAN_POINT('',(40.,-1.75,3.09));
#884=DIRECTION('',(1.,0.,0.));
#885=DIRECTION('',(0.,1.,0.));
#886=AXIS2_PLACEMENT_3D('',#883,#884,#885);
#887=CYLINDRICAL_SURFACE('',#886,6.74);
#888=CARTESIAN_POINT('',(40.,-1.75,3.09));
#889=DIRECTION('',(1.,0.,0.));
#890=DIRECTION('',(0.,1.,0.));
#891=AXIS2_PLACEMENT_3D('',#888,#889,#890);
#892=CIRCLE('',#891,6.74);
#893=CARTESIAN_POINT('',(40.,-3.12143164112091,9.68899804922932));
#894=VERTEX_POINT('',#893);
#895=EDGE_CURVE('E531',#894,#862,#892,.T.);
#896=ORIENTED_EDGE('',*,*,#895,.F.);
#897=DIRECTION('',(1.,0.,0.));
#898=VECTOR('',#897,1.);
#899=CARTESIAN_POINT('',(40.,-3.1214316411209,9.68899804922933));
#900=LINE('',#899,#898);
#901=CARTESIAN_POINT('',(38.7625,-3.12143164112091,9.68899804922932));
#902=VERTEX_POINT('',#901);
#903=EDGE_CURVE('E557',#894,#902,#900,.F.);
#904=ORIENTED_EDGE('',*,*,#903,.T.);
#905=CARTESIAN_POINT('',(38.7625,-1.75,3.09));
#906=DIRECTION('',(1.,0.,0.));
#907=DIRECTION('',(0.,1.,0.));
#908=AXIS2_PLACEMENT_3D('',#905,#906,#907);
#909=CIRCLE('',#908,6.74);
#910=EDGE_CURVE('E554',#902,#870,#909,.T.);
#911=ORIENTED_EDGE('',*,*,#910,.T.);
#912=ORIENTED_EDGE('',*,*,#871,.F.);
#913=EDGE_LOOP('',(#896,#904,#911,#912));
#914=FACE_BOUND('',#913,.T.);
#915=ADVANCED_FACE('F796',(#914),#887,.T.);
#916=CARTESIAN_POINT('',(-8.13875,15.5,0.));
#917=DIRECTION('',(1.,0.,0.));
#918=DIRECTION('',(0.,1.,0.));
#919=AXIS2_PLACEMENT_3D('',#916,#917,#918);
#920=PLANE('',#919);
#921=ORIENTED_EDGE('',*,*,#840,.F.);
#922=ORIENTED_EDGE('',*,*,#694,.F.);
#923=DIRECTION('',(0.,-0.979079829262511,-0.203476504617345));
#924=VECTOR('',#923,1.);
#925=CARTESIAN_POINT('',(-8.13875,5.5926726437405,11.2957265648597));
#926=LINE('',#925,#924);
#927=CARTESIAN_POINT('',(-8.13875,5.5926726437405,11.2957265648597));
#928=VERTEX_POINT('',#927);
#929=EDGE_CURVE('E334',#928,#684,#926,.T.);
#930=ORIENTED_EDGE('',*,*,#929,.F.);
#931=DIRECTION('',(0.,0.,1.));
#932=VECTOR('',#931,1.);
#933=CARTESIAN_POINT('',(-8.13875,5.5926726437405,10.2743593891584));
#934=LINE('',#933,#932);
#935=CARTESIAN_POINT('',(-8.13875,5.5926726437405,10.2743593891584));
#936=VERTEX_POINT('',#935);
#937=EDGE_CURVE('E324',#928,#936,#934,.F.);
#938=ORIENTED_EDGE('',*,*,#937,.T.);
#939=DIRECTION('',(0.,0.979079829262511,0.203476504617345));
#940=VECTOR('',#939,1.);
#941=CARTESIAN_POINT('',(-8.13875,-2.8772598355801,8.51410225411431));
#942=LINE('',#941,#940);
#943=EDGE_CURVE('E308',#609,#936,#942,.T.);
#944=ORIENTED_EDGE('',*,*,#943,.F.);
#945=ORIENTED_EDGE('',*,*,#610,.F.);
#946=EDGE_LOOP('',(#921,#922,#930,#938,#944,#945));
#947=FACE_BOUND('',#946,.T.);
#948=ADVANCED_FACE('F322',(#947),#920,.F.);
#949=CARTESIAN_POINT('',(38.7625,-2.8772598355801,8.51410225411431));
#950=DIRECTION('',(0.,0.203476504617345,-0.979079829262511));
#951=DIRECTION('',(0.,0.979079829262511,0.203476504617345));
#952=AXIS2_PLACEMENT_3D('',#949,#950,#951);
#953=PLANE('',#952);
#954=DIRECTION('',(1.,0.,0.));
#955=VECTOR('',#954,1.);
#956=CARTESIAN_POINT('',(38.7625,5.5926726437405,10.2743593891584));
#957=LINE('',#956,#955);
#958=CARTESIAN_POINT('',(-8.2625,5.5926726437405,10.2743593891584));
#959=VERTEX_POINT('',#958);
#960=EDGE_CURVE('E315',#959,#936,#957,.T.);
#961=ORIENTED_EDGE('',*,*,#960,.F.);
#962=DIRECTION('',(0.,0.979079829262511,0.203476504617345));
#963=VECTOR('',#962,1.);
#964=CARTESIAN_POINT('',(-8.2625,-2.8772598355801,8.51410225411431));
#965=LINE('',#964,#963);
#966=EDGE_CURVE('E311',#592,#959,#965,.T.);
#967=ORIENTED_EDGE('',*,*,#966,.F.);
#968=ORIENTED_EDGE('',*,*,#616,.F.);
#969=ORIENTED_EDGE('',*,*,#943,.T.);
#970=EDGE_LOOP('',(#961,#967,#968,#969));
#971=FACE_BOUND('',#970,.T.);
#972=ADVANCED_FACE('F306',(#971),#953,.F.);
#973=CARTESIAN_POINT('',(-8.2625,15.5,0.));
#974=DIRECTION('',(1.,0.,0.));
#975=DIRECTION('',(0.,1.,0.));
#976=AXIS2_PLACEMENT_3D('',#973,#974,#975);
#977=PLANE('',#976);
#978=ORIENTED_EDGE('',*,*,#966,.T.);
#979=DIRECTION('',(0.,0.,1.));
#980=VECTOR('',#979,1.);
#981=CARTESIAN_POINT('',(-8.2625,5.5926726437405,10.2743593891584));
#982=LINE('',#981,#980);
#983=CARTESIAN_POINT('',(-8.2625,5.59267264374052,11.5));
#984=VERTEX_POINT('',#983);
#985=EDGE_CURVE('E656',#959,#984,#982,.T.);
#986=ORIENTED_EDGE('',*,*,#985,.T.);
#987=DIRECTION('',(0.,-0.979079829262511,-0.203476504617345));
#988=VECTOR('',#987,1.);
#989=CARTESIAN_POINT('',(-8.2625,5.59267264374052,11.5));
#990=LINE('',#989,#988);
#991=EDGE_CURVE('E397',#735,#984,#990,.F.);
#992=ORIENTED_EDGE('',*,*,#991,.F.);
#993=ORIENTED_EDGE('',*,*,#736,.F.);
#994=ORIENTED_EDGE('',*,*,#847,.T.);
#995=ORIENTED_EDGE('',*,*,#593,.T.);
#996=EDGE_LOOP('',(#978,#986,#992,#993,#994,#995));
#997=FACE_BOUND('',#996,.T.);
#998=ADVANCED_FACE('F658',(#997),#977,.T.);
#999=CARTESIAN_POINT('',(38.7625,15.5,0.));
#1000=DIRECTION('',(1.,0.,0.));
#1001=DIRECTION('',(0.,1.,0.));
#1002=AXIS2_PLACEMENT_3D('',#999,#1000,#1001);
#1003=PLANE('',#1002);
#1004=DIRECTION('',(0.,0.,1.));
#1005=VECTOR('',#1004,1.);
#1006=CARTESIAN_POINT('',(38.7625,5.5926726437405,0.));
#1007=LINE('',#1006,#1005);
#1008=CARTESIAN_POINT('',(38.7625,5.5926726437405,10.2743593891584));
#1009=VERTEX_POINT('',#1008);
#1010=CARTESIAN_POINT('',(38.7625,5.5926726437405,11.5));
#1011=VERTEX_POINT('',#1010);
#1012=EDGE_CURVE('E595',#1009,#1011,#1007,.T.);
#1013=ORIENTED_EDGE('',*,*,#1012,.F.);
#1014=DIRECTION('',(0.,0.979079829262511,0.203476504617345));
#1015=VECTOR('',#1014,1.);
#1016=CARTESIAN_POINT('',(38.7625,-2.8772598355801,8.51410225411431));
#1017=LINE('',#1016,#1015);
#1018=EDGE_CURVE('E598',#634,#1009,#1017,.T.);
#1019=ORIENTED_EDGE('',*,*,#1018,.F.);
#1020=ORIENTED_EDGE('',*,*,#635,.F.);
#1021=ORIENTED_EDGE('',*,*,#877,.F.);
#1022=ORIENTED_EDGE('',*,*,#910,.F.);
#1023=DIRECTION('',(0.,-0.979079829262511,-0.203476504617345));
#1024=VECTOR('',#1023,1.);
#1025=CARTESIAN_POINT('',(38.7625,5.59267264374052,11.5));
#1026=LINE('',#1025,#1024);
#1027=EDGE_CURVE('E562',#1011,#902,#1026,.T.);
#1028=ORIENTED_EDGE('',*,*,#1027,.F.);
#1029=EDGE_LOOP('',(#1013,#1019,#1020,#1021,#1022,#1028));
#1030=FACE_BOUND('',#1029,.T.);
#1031=ADVANCED_FACE('F843',(#1030),#1003,.F.);
#1032=CARTESIAN_POINT('',(38.7625,-2.8772598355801,8.51410225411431));
#1033=DIRECTION('',(0.,0.203476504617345,-0.979079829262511));
#1034=DIRECTION('',(0.,0.979079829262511,0.203476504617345));
#1035=AXIS2_PLACEMENT_3D('',#1032,#1033,#1034);
#1036=PLANE('',#1035);
#1037=ORIENTED_EDGE('',*,*,#643,.F.);
#1038=ORIENTED_EDGE('',*,*,#1018,.T.);
#1039=DIRECTION('',(-1.,0.,0.));
#1040=VECTOR('',#1039,1.);
#1041=CARTESIAN_POINT('',(38.7625,5.5926726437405,10.2743593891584));
#1042=LINE('',#1041,#1040);
#1043=CARTESIAN_POINT('',(38.63875,5.5926726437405,10.2743593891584));
#1044=VERTEX_POINT('',#1043);
#1045=EDGE_CURVE('E341',#1009,#1044,#1042,.T.);
#1046=ORIENTED_EDGE('',*,*,#1045,.T.);
#1047=DIRECTION('',(0.,0.979079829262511,0.203476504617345));
#1048=VECTOR('',#1047,1.);
#1049=CARTESIAN_POINT('',(38.63875,-2.8772598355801,8.51410225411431));
#1050=LINE('',#1049,#1048);
#1051=EDGE_CURVE('E338',#642,#1044,#1050,.T.);
#1052=ORIENTED_EDGE('',*,*,#1051,.F.);
#1053=EDGE_LOOP('',(#1037,#1038,#1046,#1052));
#1054=FACE_BOUND('',#1053,.T.);
#1055=ADVANCED_FACE('F846',(#1054),#1036,.F.);
#1056=CARTESIAN_POINT('',(38.63875,15.5,0.));
#1057=DIRECTION('',(1.,0.,0.));
#1058=DIRECTION('',(0.,1.,0.));
#1059=AXIS2_PLACEMENT_3D('',#1056,#1057,#1058);
#1060=PLANE('',#1059);
#1061=DIRECTION('',(0.,-0.979079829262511,-0.203476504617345));
#1062=VECTOR('',#1061,1.);
#1063=CARTESIAN_POINT('',(38.63875,5.5926726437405,11.2957265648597));
#1064=LINE('',#1063,#1062);
#1065=CARTESIAN_POINT('',(38.63875,5.5926726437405,11.2957265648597));
#1066=VERTEX_POINT('',#1065);
#1067=EDGE_CURVE('E337',#676,#1066,#1064,.F.);
#1068=ORIENTED_EDGE('',*,*,#1067,.F.);
#1069=ORIENTED_EDGE('',*,*,#677,.F.);
#1070=ORIENTED_EDGE('',*,*,#833,.T.);
#1071=ORIENTED_EDGE('',*,*,#652,.T.);
#1072=ORIENTED_EDGE('',*,*,#1051,.T.);
#1073=DIRECTION('',(0.,0.,1.));
#1074=VECTOR('',#1073,1.);
#1075=CARTESIAN_POINT('',(38.63875,5.5926726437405,10.2743593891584));
#1076=LINE('',#1075,#1074);
#1077=EDGE_CURVE('E343',#1044,#1066,#1076,.T.);
#1078=ORIENTED_EDGE('',*,*,#1077,.T.);
#1079=EDGE_LOOP('',(#1068,#1069,#1070,#1071,#1072,#1078));
#1080=FACE_BOUND('',#1079,.T.);
#1081=ADVANCED_FACE('F951',(#1080),#1060,.T.);
#1082=CARTESIAN_POINT('',(38.63875,5.5926726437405,11.2957265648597));
#1083=DIRECTION('',(0.,-0.203476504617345,0.979079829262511));
#1084=DIRECTION('',(0.,-0.979079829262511,-0.203476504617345));
#1085=AXIS2_PLACEMENT_3D('',#1082,#1083,#1084);
#1086=PLANE('',#1085);
#1087=ORIENTED_EDGE('',*,*,#1067,.T.);
#1088=DIRECTION('',(-1.,0.,0.));
#1089=VECTOR('',#1088,1.);
#1090=CARTESIAN_POINT('',(38.7625,5.5926726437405,11.2957265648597));
#1091=LINE('',#1090,#1089);
#1092=EDGE_CURVE('E358',#1066,#928,#1091,.T.);
#1093=ORIENTED_EDGE('',*,*,#1092,.T.);
#1094=ORIENTED_EDGE('',*,*,#929,.T.);
#1095=ORIENTED_EDGE('',*,*,#685,.F.);
#1096=EDGE_LOOP('',(#1087,#1093,#1094,#1095));
#1097=FACE_BOUND('',#1096,.T.);
#1098=ADVANCED_FACE('F649',(#1097),#1086,.T.);
#1099=CARTESIAN_POINT('',(-9.5,15.5,0.));
#1100=DIRECTION('',(1.,0.,0.));
#1101=DIRECTION('',(0.,1.,0.));
#1102=AXIS2_PLACEMENT_3D('',#1099,#1100,#1101);
#1103=PLANE('',#1102);
#1104=ORIENTED_EDGE('',*,*,#776,.F.);
#1105=ORIENTED_EDGE('',*,*,#818,.F.);
#1106=ORIENTED_EDGE('',*,*,#854,.F.);
#1107=ORIENTED_EDGE('',*,*,#719,.F.);
#1108=DIRECTION('',(0.,-0.979079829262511,-0.203476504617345));
#1109=VECTOR('',#1108,1.);
#1110=CARTESIAN_POINT('',(-9.5,5.59267264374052,11.5));
#1111=LINE('',#1110,#1109);
#1112=CARTESIAN_POINT('',(-9.5,5.59267264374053,11.5));
#1113=VERTEX_POINT('',#1112);
#1114=EDGE_CURVE('E543',#1113,#716,#1111,.T.);
#1115=ORIENTED_EDGE('',*,*,#1114,.F.);
#1116=CARTESIAN_POINT('',(-9.5,-8.8700000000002,-9.1));
#1117=DIRECTION('',(1.,0.,0.));
#1118=DIRECTION('',(0.,1.,0.));
#1119=AXIS2_PLACEMENT_3D('',#1116,#1117,#1118);
#1120=CIRCLE('',#1119,25.17);
#1121=CARTESIAN_POINT('',(-9.5,13.,3.35921345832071));
#1122=VERTEX_POINT('',#1121);
#1123=EDGE_CURVE('E544',#1122,#1113,#1120,.T.);
#1124=ORIENTED_EDGE('',*,*,#1123,.F.);
#1125=DIRECTION('',(0.,0.,1.));
#1126=VECTOR('',#1125,1.);
#1127=CARTESIAN_POINT('',(-9.5,13.,0.));
#1128=LINE('',#1127,#1126);
#1129=EDGE_CURVE('E1378',#775,#1122,#1128,.T.);
#1130=ORIENTED_EDGE('',*,*,#1129,.F.);
#1131=EDGE_LOOP('',(#1104,#1105,#1106,#1107,#1115,#1124,#1130));
#1132=FACE_BOUND('',#1131,.T.);
#1133=ADVANCED_FACE('F781',(#1132),#1103,.F.);
#1134=CARTESIAN_POINT('',(40.,5.59267264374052,11.5));
#1135=DIRECTION('',(0.,-0.203476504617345,0.979079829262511));
#1136=DIRECTION('',(0.,-0.979079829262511,-0.203476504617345));
#1137=AXIS2_PLACEMENT_3D('',#1134,#1135,#1136);
#1138=PLANE('',#1137);
#1139=ORIENTED_EDGE('',*,*,#1114,.T.);
#1140=ORIENTED_EDGE('',*,*,#742,.F.);
#1141=ORIENTED_EDGE('',*,*,#991,.T.);
#1142=DIRECTION('',(1.,0.,0.));
#1143=VECTOR('',#1142,1.);
#1144=CARTESIAN_POINT('',(40.,5.59267264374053,11.5));
#1145=LINE('',#1144,#1143);
#1146=EDGE_CURVE('E584',#1113,#984,#1145,.T.);
#1147=ORIENTED_EDGE('',*,*,#1146,.F.);
#1148=EDGE_LOOP('',(#1139,#1140,#1141,#1147));
#1149=FACE_BOUND('',#1148,.T.);
#1150=ADVANCED_FACE('F767',(#1149),#1138,.T.);
#1151=CARTESIAN_POINT('',(40.,13.,0.));
#1152=DIRECTION('',(0.,1.,0.));
#1153=DIRECTION('',(-1.,0.,0.));
#1154=AXIS2_PLACEMENT_3D('',#1151,#1152,#1153);
#1155=PLANE('',#1154);
#1156=DIRECTION('',(0.,0.,1.));
#1157=VECTOR('',#1156,1.);
#1158=CARTESIAN_POINT('',(40.,13.,0.));
#1159=LINE('',#1158,#1157);
#1160=CARTESIAN_POINT('',(40.,13.,3.3592134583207));
#1161=VERTEX_POINT('',#1160);
#1162=EDGE_CURVE('E539',#757,#1161,#1159,.T.);
#1163=ORIENTED_EDGE('',*,*,#1162,.F.);
#1164=ORIENTED_EDGE('',*,*,#782,.F.);
#1165=ORIENTED_EDGE('',*,*,#1129,.T.);
#1166=DIRECTION('',(-1.,0.,0.));
#1167=VECTOR('',#1166,1.);
#1168=CARTESIAN_POINT('',(40.,13.,3.35921345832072));
#1169=LINE('',#1168,#1167);
#1170=CARTESIAN_POINT('',(-1.35,13.,3.35921345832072));
#1171=VERTEX_POINT('',#1170);
#1172=EDGE_CURVE('E1431',#1122,#1171,#1169,.F.);
#1173=ORIENTED_EDGE('',*,*,#1172,.T.);
#1174=DIRECTION('',(-1.,0.,0.));
#1175=VECTOR('',#1174,1.);
#1176=CARTESIAN_POINT('',(40.,13.,3.35921345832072));
#1177=LINE('',#1176,#1175);
#1178=CARTESIAN_POINT('',(6.8,13.,3.35921345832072));
#1179=VERTEX_POINT('',#1178);
#1180=EDGE_CURVE('E1428',#1171,#1179,#1177,.F.);
#1181=ORIENTED_EDGE('',*,*,#1180,.T.);
#1182=DIRECTION('',(-1.,0.,0.));
#1183=VECTOR('',#1182,1.);
#1184=CARTESIAN_POINT('',(40.,13.,3.35921345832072));
#1185=LINE('',#1184,#1183);
#1186=CARTESIAN_POINT('',(15.35,13.,3.35921345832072));
#1187=VERTEX_POINT('',#1186);
#1188=EDGE_CURVE('E1420',#1179,#1187,#1185,.F.);
#1189=ORIENTED_EDGE('',*,*,#1188,.T.);
#1190=DIRECTION('',(-1.,0.,0.));
#1191=VECTOR('',#1190,1.);
#1192=CARTESIAN_POINT('',(40.,13.,3.35921345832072));
#1193=LINE('',#1192,#1191);
#1194=CARTESIAN_POINT('',(23.5,13.,3.35921345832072));
#1195=VERTEX_POINT('',#1194);
#1196=EDGE_CURVE('E1417',#1187,#1195,#1193,.F.);
#1197=ORIENTED_EDGE('',*,*,#1196,.T.);
#1198=DIRECTION('',(-1.,0.,0.));
#1199=VECTOR('',#1198,1.);
#1200=CARTESIAN_POINT('',(40.,13.,3.35921345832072));
#1201=LINE('',#1200,#1199);
#1202=CARTESIAN_POINT('',(32.05,13.,3.35921345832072));
#1203=VERTEX_POINT('',#1202);
#1204=EDGE_CURVE('E1408',#1195,#1203,#1201,.F.);
#1205=ORIENTED_EDGE('',*,*,#1204,.T.);
#1206=DIRECTION('',(-1.,0.,0.));
#1207=VECTOR('',#1206,1.);
#1208=CARTESIAN_POINT('',(40.,13.,3.35921345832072));
#1209=LINE('',#1208,#1207);
#1210=CARTESIAN_POINT('',(39.35,13.,3.35921345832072));
#1211=VERTEX_POINT('',#1210);
#1212=EDGE_CURVE('E1397',#1203,#1211,#1209,.F.);
#1213=ORIENTED_EDGE('',*,*,#1212,.T.);
#1214=DIRECTION('',(-1.,0.,0.));
#1215=VECTOR('',#1214,1.);
#1216=CARTESIAN_POINT('',(40.,13.,3.35921345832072));
#1217=LINE('',#1216,#1215);
#1218=EDGE_CURVE('E1374',#1211,#1161,#1217,.F.);
#1219=ORIENTED_EDGE('',*,*,#1218,.T.);
#1220=EDGE_LOOP('',(#1163,#1164,#1165,#1173,#1181,#1189,#1197,#1205,#1213,#1219));
#1221=FACE_BOUND('',#1220,.T.);
#1222=ADVANCED_FACE('F777',(#1221),#1155,.T.);
#1223=CARTESIAN_POINT('',(40.,15.5,0.));
#1224=DIRECTION('',(1.,0.,0.));
#1225=DIRECTION('',(0.,1.,0.));
#1226=AXIS2_PLACEMENT_3D('',#1223,#1224,#1225);
#1227=PLANE('',#1226);
#1228=ORIENTED_EDGE('',*,*,#863,.T.);
#1229=ORIENTED_EDGE('',*,*,#804,.F.);
#1230=ORIENTED_EDGE('',*,*,#760,.F.);
#1231=ORIENTED_EDGE('',*,*,#1162,.T.);
#1232=CARTESIAN_POINT('',(40.,-8.8700000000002,-9.1));
#1233=DIRECTION('',(1.,0.,0.));
#1234=DIRECTION('',(0.,1.,0.));
#1235=AXIS2_PLACEMENT_3D('',#1232,#1233,#1234);
#1236=CIRCLE('',#1235,25.17);
#1237=CARTESIAN_POINT('',(40.,5.59267264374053,11.5));
#1238=VERTEX_POINT('',#1237);
#1239=EDGE_CURVE('E536',#1161,#1238,#1236,.T.);
#1240=ORIENTED_EDGE('',*,*,#1239,.T.);
#1241=DIRECTION('',(0.,-0.979079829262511,-0.203476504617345));
#1242=VECTOR('',#1241,1.);
#1243=CARTESIAN_POINT('',(40.,5.59267264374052,11.5));
#1244=LINE('',#1243,#1242);
#1245=EDGE_CURVE('E535',#1238,#894,#1244,.T.);
#1246=ORIENTED_EDGE('',*,*,#1245,.T.);
#1247=ORIENTED_EDGE('',*,*,#895,.T.);
#1248=EDGE_LOOP('',(#1228,#1229,#1230,#1231,#1240,#1246,#1247));
#1249=FACE_BOUND('',#1248,.T.);
#1250=ADVANCED_FACE('F763',(#1249),#1227,.T.);
#1251=CARTESIAN_POINT('',(40.,5.59267264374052,11.5));
#1252=DIRECTION('',(0.,-0.203476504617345,0.979079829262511));
#1253=DIRECTION('',(0.,-0.979079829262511,-0.203476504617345));
#1254=AXIS2_PLACEMENT_3D('',#1251,#1252,#1253);
#1255=PLANE('',#1254);
#1256=DIRECTION('',(1.,0.,0.));
#1257=VECTOR('',#1256,1.);
#1258=CARTESIAN_POINT('',(40.,5.59267264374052,11.5));
#1259=LINE('',#1258,#1257);
#1260=CARTESIAN_POINT('',(39.35,5.59267264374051,11.5));
#1261=VERTEX_POINT('',#1260);
#1262=EDGE_CURVE('E558',#1238,#1261,#1259,.F.);
#1263=ORIENTED_EDGE('',*,*,#1262,.T.);
#1264=DIRECTION('',(1.,0.,0.));
#1265=VECTOR('',#1264,1.);
#1266=CARTESIAN_POINT('',(32.05,5.5926726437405,11.5));
#1267=LINE('',#1266,#1265);
#1268=EDGE_CURVE('E349',#1011,#1261,#1267,.T.);
#1269=ORIENTED_EDGE('',*,*,#1268,.F.);
#1270=ORIENTED_EDGE('',*,*,#1027,.T.);
#1271=ORIENTED_EDGE('',*,*,#903,.F.);
#1272=ORIENTED_EDGE('',*,*,#1245,.F.);
#1273=EDGE_LOOP('',(#1263,#1269,#1270,#1271,#1272));
#1274=FACE_BOUND('',#1273,.T.);
#1275=ADVANCED_FACE('F776',(#1274),#1255,.T.);
#1276=CARTESIAN_POINT('',(38.7625,5.5926726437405,10.2743593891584));
#1277=DIRECTION('',(0.,1.,0.));
#1278=DIRECTION('',(-1.,0.,0.));
#1279=AXIS2_PLACEMENT_3D('',#1276,#1277,#1278);
#1280=PLANE('',#1279);
#1281=ORIENTED_EDGE('',*,*,#1092,.F.);
#1282=ORIENTED_EDGE('',*,*,#1077,.F.);
#1283=ORIENTED_EDGE('',*,*,#1045,.F.);
#1284=ORIENTED_EDGE('',*,*,#1012,.T.);
#1285=DIRECTION('',(-1.,0.,0.));
#1286=VECTOR('',#1285,1.);
#1287=CARTESIAN_POINT('',(38.7625,5.5926726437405,11.5));
#1288=LINE('',#1287,#1286);
#1289=CARTESIAN_POINT('',(32.05,5.59267264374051,11.5));
#1290=VERTEX_POINT('',#1289);
#1291=EDGE_CURVE('E344',#1290,#1011,#1288,.F.);
#1292=ORIENTED_EDGE('',*,*,#1291,.F.);
#1293=DIRECTION('',(1.,0.,0.));
#1294=VECTOR('',#1293,1.);
#1295=CARTESIAN_POINT('',(40.,5.59267264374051,11.5));
#1296=LINE('',#1295,#1294);
#1297=CARTESIAN_POINT('',(23.5,5.59267264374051,11.5));
#1298=VERTEX_POINT('',#1297);
#1299=EDGE_CURVE('E567',#1298,#1290,#1296,.T.);
#1300=ORIENTED_EDGE('',*,*,#1299,.F.);
#1301=DIRECTION('',(-1.,0.,0.));
#1302=VECTOR('',#1301,1.);
#1303=CARTESIAN_POINT('',(38.7625,5.5926726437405,11.5));
#1304=LINE('',#1303,#1302);
#1305=CARTESIAN_POINT('',(15.35,5.59267264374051,11.5));
#1306=VERTEX_POINT('',#1305);
#1307=EDGE_CURVE('E1482',#1306,#1298,#1304,.F.);
#1308=ORIENTED_EDGE('',*,*,#1307,.F.);
#1309=DIRECTION('',(1.,0.,0.));
#1310=VECTOR('',#1309,1.);
#1311=CARTESIAN_POINT('',(40.,5.59267264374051,11.5));
#1312=LINE('',#1311,#1310);
#1313=CARTESIAN_POINT('',(6.8,5.59267264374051,11.5));
#1314=VERTEX_POINT('',#1313);
#1315=EDGE_CURVE('E576',#1314,#1306,#1312,.T.);
#1316=ORIENTED_EDGE('',*,*,#1315,.F.);
#1317=DIRECTION('',(-1.,0.,0.));
#1318=VECTOR('',#1317,1.);
#1319=CARTESIAN_POINT('',(38.7625,5.5926726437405,11.5));
#1320=LINE('',#1319,#1318);
#1321=CARTESIAN_POINT('',(-1.35,5.59267264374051,11.5));
#1322=VERTEX_POINT('',#1321);
#1323=EDGE_CURVE('E1484',#1322,#1314,#1320,.F.);
#1324=ORIENTED_EDGE('',*,*,#1323,.F.);
#1325=DIRECTION('',(1.,0.,0.));
#1326=VECTOR('',#1325,1.);
#1327=CARTESIAN_POINT('',(40.,5.59267264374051,11.5));
#1328=LINE('',#1327,#1326);
#1329=EDGE_CURVE('E1438',#984,#1322,#1328,.T.);
#1330=ORIENTED_EDGE('',*,*,#1329,.F.);
#1331=ORIENTED_EDGE('',*,*,#985,.F.);
#1332=ORIENTED_EDGE('',*,*,#960,.T.);
#1333=ORIENTED_EDGE('',*,*,#937,.F.);
#1334=EDGE_LOOP('',(#1281,#1282,#1283,#1284,#1292,#1300,#1308,#1316,#1324,#1330,#1331,#1332,#1333));
#1335=FACE_BOUND('',#1334,.T.);
#1336=ADVANCED_FACE('F652',(#1335),#1280,.F.);
#1337=CARTESIAN_POINT('',(40.,-8.8700000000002,-9.1));
#1338=DIRECTION('',(1.,0.,0.));
#1339=DIRECTION('',(0.,1.,0.));
#1340=AXIS2_PLACEMENT_3D('',#1337,#1338,#1339);
#1341=CYLINDRICAL_SURFACE('',#1340,25.17);
#1342=ORIENTED_EDGE('',*,*,#1146,.T.);
#1343=ORIENTED_EDGE('',*,*,#1329,.T.);
#1344=CARTESIAN_POINT('',(-1.35,-8.8700000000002,-9.1));
#1345=DIRECTION('',(1.,0.,0.));
#1346=DIRECTION('',(0.,1.,0.));
#1347=AXIS2_PLACEMENT_3D('',#1344,#1345,#1346);
#1348=CIRCLE('',#1347,25.17);
#1349=EDGE_CURVE('E581',#1322,#1171,#1348,.F.);
#1350=ORIENTED_EDGE('',*,*,#1349,.T.);
#1351=ORIENTED_EDGE('',*,*,#1172,.F.);
#1352=ORIENTED_EDGE('',*,*,#1123,.T.);
#1353=EDGE_LOOP('',(#1342,#1343,#1350,#1351,#1352));
#1354=FACE_BOUND('',#1353,.T.);
#1355=ADVANCED_FACE('F768',(#1354),#1341,.T.);
#1356=CARTESIAN_POINT('',(6.8,13.,3.35921345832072));
#1357=DIRECTION('',(0.,0.601465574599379,-0.798898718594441));
#1358=DIRECTION('',(0.,0.798898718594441,0.601465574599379));
#1359=AXIS2_PLACEMENT_3D('',#1356,#1357,#1358);
#1360=PLANE('',#1359);
#1361=DIRECTION('',(0.,0.798898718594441,0.601465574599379));
#1362=VECTOR('',#1361,1.);
#1363=CARTESIAN_POINT('',(6.8,13.,3.35921345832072));
#1364=LINE('',#1363,#1362);
#1365=CARTESIAN_POINT('',(6.8,18.5073278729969,7.5055064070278));
#1366=VERTEX_POINT('',#1365);
#1367=EDGE_CURVE('E580',#1366,#1179,#1364,.F.);
#1368=ORIENTED_EDGE('',*,*,#1367,.T.);
#1369=ORIENTED_EDGE('',*,*,#1180,.F.);
#1370=DIRECTION('',(0.,0.798898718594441,0.601465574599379));
#1371=VECTOR('',#1370,1.);
#1372=CARTESIAN_POINT('',(-1.35,13.,3.35921345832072));
#1373=LINE('',#1372,#1371);
#1374=CARTESIAN_POINT('',(-1.35,18.5073278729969,7.5055064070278));
#1375=VERTEX_POINT('',#1374);
#1376=EDGE_CURVE('E1435',#1171,#1375,#1373,.T.);
#1377=ORIENTED_EDGE('',*,*,#1376,.T.);
#1378=DIRECTION('',(1.,0.,0.));
#1379=VECTOR('',#1378,1.);
#1380=CARTESIAN_POINT('',(6.8,18.5073278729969,7.5055064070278));
#1381=LINE('',#1380,#1379);
#1382=EDGE_CURVE('E1434',#1375,#1366,#1381,.T.);
#1383=ORIENTED_EDGE('',*,*,#1382,.T.);
#1384=EDGE_LOOP('',(#1368,#1369,#1377,#1383));
#1385=FACE_BOUND('',#1384,.T.);
#1386=ADVANCED_FACE('F823',(#1385),#1360,.T.);
#1387=CARTESIAN_POINT('',(40.,-8.8700000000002,-9.1));
#1388=DIRECTION('',(1.,0.,0.));
#1389=DIRECTION('',(0.,1.,0.));
#1390=AXIS2_PLACEMENT_3D('',#1387,#1388,#1389);
#1391=CYLINDRICAL_SURFACE('',#1390,25.17);
#1392=CARTESIAN_POINT('',(15.35,-8.8700000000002,-9.1));
#1393=DIRECTION('',(1.,0.,0.));
#1394=DIRECTION('',(0.,1.,0.));
#1395=AXIS2_PLACEMENT_3D('',#1392,#1393,#1394);
#1396=CIRCLE('',#1395,25.17);
#1397=EDGE_CURVE('E572',#1306,#1187,#1396,.F.);
#1398=ORIENTED_EDGE('',*,*,#1397,.T.);
#1399=ORIENTED_EDGE('',*,*,#1188,.F.);
#1400=CARTESIAN_POINT('',(6.8,-8.8700000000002,-9.1));
#1401=DIRECTION('',(1.,0.,0.));
#1402=DIRECTION('',(0.,1.,0.));
#1403=AXIS2_PLACEMENT_3D('',#1400,#1401,#1402);
#1404=CIRCLE('',#1403,25.17);
#1405=EDGE_CURVE('E577',#1179,#1314,#1404,.T.);
#1406=ORIENTED_EDGE('',*,*,#1405,.T.);
#1407=ORIENTED_EDGE('',*,*,#1315,.T.);
#1408=EDGE_LOOP('',(#1398,#1399,#1406,#1407));
#1409=FACE_BOUND('',#1408,.T.);
#1410=ADVANCED_FACE('F819',(#1409),#1391,.T.);
#1411=CARTESIAN_POINT('',(15.35,18.5073278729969,7.5055064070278));
#1412=DIRECTION('',(0.,0.601465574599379,-0.798898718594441));
#1413=DIRECTION('',(0.,0.798898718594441,0.601465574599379));
#1414=AXIS2_PLACEMENT_3D('',#1411,#1412,#1413);
#1415=PLANE('',#1414);
#1416=DIRECTION('',(0.,0.798898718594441,0.601465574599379));
#1417=VECTOR('',#1416,1.);
#1418=CARTESIAN_POINT('',(15.35,18.5073278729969,7.5055064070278));
#1419=LINE('',#1418,#1417);
#1420=CARTESIAN_POINT('',(15.35,18.5073278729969,7.5055064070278));
#1421=VERTEX_POINT('',#1420);
#1422=EDGE_CURVE('E1423',#1187,#1421,#1419,.T.);
#1423=ORIENTED_EDGE('',*,*,#1422,.T.);
#1424=DIRECTION('',(1.,0.,0.));
#1425=VECTOR('',#1424,1.);
#1426=CARTESIAN_POINT('',(15.35,18.5073278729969,7.5055064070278));
#1427=LINE('',#1426,#1425);
#1428=CARTESIAN_POINT('',(23.5,18.5073278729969,7.5055064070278));
#1429=VERTEX_POINT('',#1428);
#1430=EDGE_CURVE('E571',#1421,#1429,#1427,.T.);
#1431=ORIENTED_EDGE('',*,*,#1430,.T.);
#1432=DIRECTION('',(0.,0.798898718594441,0.601465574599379));
#1433=VECTOR('',#1432,1.);
#1434=CARTESIAN_POINT('',(23.5,18.5073278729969,7.5055064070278));
#1435=LINE('',#1434,#1433);
#1436=EDGE_CURVE('E575',#1429,#1195,#1435,.F.);
#1437=ORIENTED_EDGE('',*,*,#1436,.T.);
#1438=ORIENTED_EDGE('',*,*,#1196,.F.);
#1439=EDGE_LOOP('',(#1423,#1431,#1437,#1438));
#1440=FACE_BOUND('',#1439,.T.);
#1441=ADVANCED_FACE('F815',(#1440),#1415,.T.);
#1442=CARTESIAN_POINT('',(40.,-8.8700000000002,-9.1));
#1443=DIRECTION('',(1.,0.,0.));
#1444=DIRECTION('',(0.,1.,0.));
#1445=AXIS2_PLACEMENT_3D('',#1442,#1443,#1444);
#1446=CYLINDRICAL_SURFACE('',#1445,25.17);
#1447=CARTESIAN_POINT('',(23.5,-8.8700000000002,-9.1));
#1448=DIRECTION('',(1.,0.,0.));
#1449=DIRECTION('',(0.,1.,0.));
#1450=AXIS2_PLACEMENT_3D('',#1447,#1448,#1449);
#1451=CIRCLE('',#1450,25.17);
#1452=EDGE_CURVE('E564',#1195,#1298,#1451,.T.);
#1453=ORIENTED_EDGE('',*,*,#1452,.T.);
#1454=ORIENTED_EDGE('',*,*,#1299,.T.);
#1455=CARTESIAN_POINT('',(32.05,-8.8700000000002,-9.1));
#1456=DIRECTION('',(1.,0.,0.));
#1457=DIRECTION('',(0.,1.,0.));
#1458=AXIS2_PLACEMENT_3D('',#1455,#1456,#1457);
#1459=CIRCLE('',#1458,25.17);
#1460=EDGE_CURVE('E568',#1290,#1203,#1459,.F.);
#1461=ORIENTED_EDGE('',*,*,#1460,.T.);
#1462=ORIENTED_EDGE('',*,*,#1204,.F.);
#1463=EDGE_LOOP('',(#1453,#1454,#1461,#1462));
#1464=FACE_BOUND('',#1463,.T.);
#1465=ADVANCED_FACE('F811',(#1464),#1446,.T.);
#1466=CARTESIAN_POINT('',(32.05,18.5073278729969,7.5055064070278));
#1467=DIRECTION('',(0.,0.601465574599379,-0.798898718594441));
#1468=DIRECTION('',(0.,0.798898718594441,0.601465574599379));
#1469=AXIS2_PLACEMENT_3D('',#1466,#1467,#1468);
#1470=PLANE('',#1469);
#1471=DIRECTION('',(0.,0.798898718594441,0.601465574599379));
#1472=VECTOR('',#1471,1.);
#1473=CARTESIAN_POINT('',(32.05,18.5073278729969,7.5055064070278));
#1474=LINE('',#1473,#1472);
#1475=CARTESIAN_POINT('',(32.05,18.5073278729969,7.5055064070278));
#1476=VERTEX_POINT('',#1475);
#1477=EDGE_CURVE('E1412',#1203,#1476,#1474,.T.);
#1478=ORIENTED_EDGE('',*,*,#1477,.T.);
#1479=DIRECTION('',(1.,0.,0.));
#1480=VECTOR('',#1479,1.);
#1481=CARTESIAN_POINT('',(32.05,18.5073278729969,7.5055064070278));
#1482=LINE('',#1481,#1480);
#1483=CARTESIAN_POINT('',(39.35,18.5073278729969,7.5055064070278));
#1484=VERTEX_POINT('',#1483);
#1485=EDGE_CURVE('E563',#1476,#1484,#1482,.T.);
#1486=ORIENTED_EDGE('',*,*,#1485,.T.);
#1487=DIRECTION('',(0.,0.798898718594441,0.601465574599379));
#1488=VECTOR('',#1487,1.);
#1489=CARTESIAN_POINT('',(39.35,18.5073278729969,7.5055064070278));
#1490=LINE('',#1489,#1488);
#1491=EDGE_CURVE('E1409',#1484,#1211,#1490,.F.);
#1492=ORIENTED_EDGE('',*,*,#1491,.T.);
#1493=ORIENTED_EDGE('',*,*,#1212,.F.);
#1494=EDGE_LOOP('',(#1478,#1486,#1492,#1493));
#1495=FACE_BOUND('',#1494,.T.);
#1496=ADVANCED_FACE('F807',(#1495),#1470,.T.);
#1497=CARTESIAN_POINT('',(40.,-8.8700000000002,-9.1));
#1498=DIRECTION('',(1.,0.,0.));
#1499=DIRECTION('',(0.,1.,0.));
#1500=AXIS2_PLACEMENT_3D('',#1497,#1498,#1499);
#1501=CYLINDRICAL_SURFACE('',#1500,25.17);
#1502=ORIENTED_EDGE('',*,*,#1239,.F.);
#1503=ORIENTED_EDGE('',*,*,#1218,.F.);
#1504=CARTESIAN_POINT('',(39.35,-8.8700000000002,-9.1));
#1505=DIRECTION('',(1.,0.,0.));
#1506=DIRECTION('',(0.,1.,0.));
#1507=AXIS2_PLACEMENT_3D('',#1504,#1505,#1506);
#1508=CIRCLE('',#1507,25.17);
#1509=EDGE_CURVE('E559',#1211,#1261,#1508,.T.);
#1510=ORIENTED_EDGE('',*,*,#1509,.T.);
#1511=ORIENTED_EDGE('',*,*,#1262,.F.);
#1512=EDGE_LOOP('',(#1502,#1503,#1510,#1511));
#1513=FACE_BOUND('',#1512,.T.);
#1514=ADVANCED_FACE('F803',(#1513),#1501,.T.);
#1515=CARTESIAN_POINT('',(32.05,5.5926726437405,11.5));
#1516=DIRECTION('',(0.,-0.504676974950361,0.863308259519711));
#1517=DIRECTION('',(0.,-0.863308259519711,-0.504676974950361));
#1518=AXIS2_PLACEMENT_3D('',#1515,#1516,#1517);
#1519=PLANE('',#1518);
#1520=ORIENTED_EDGE('',*,*,#1291,.T.);
#1521=ORIENTED_EDGE('',*,*,#1268,.T.);
#1522=DIRECTION('',(0.,-0.863308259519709,-0.504676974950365));
#1523=VECTOR('',#1522,1.);
#1524=CARTESIAN_POINT('',(39.35,12.9766151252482,15.8165412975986));
#1525=LINE('',#1524,#1523);
#1526=CARTESIAN_POINT('',(39.35,12.9766151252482,15.8165412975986));
#1527=VERTEX_POINT('',#1526);
#1528=EDGE_CURVE('E602',#1527,#1261,#1525,.T.);
#1529=ORIENTED_EDGE('',*,*,#1528,.F.);
#1530=DIRECTION('',(-1.,0.,0.));
#1531=VECTOR('',#1530,1.);
#1532=CARTESIAN_POINT('',(32.05,12.9766151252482,15.8165412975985));
#1533=LINE('',#1532,#1531);
#1534=CARTESIAN_POINT('',(32.05,12.9766151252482,15.8165412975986));
#1535=VERTEX_POINT('',#1534);
#1536=EDGE_CURVE('E353',#1535,#1527,#1533,.F.);
#1537=ORIENTED_EDGE('',*,*,#1536,.F.);
#1538=DIRECTION('',(0.,-0.863308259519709,-0.504676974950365));
#1539=VECTOR('',#1538,1.);
#1540=CARTESIAN_POINT('',(32.05,12.9766151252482,15.8165412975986));
#1541=LINE('',#1540,#1539);
#1542=EDGE_CURVE('E520',#1535,#1290,#1541,.T.);
#1543=ORIENTED_EDGE('',*,*,#1542,.T.);
#1544=EDGE_LOOP('',(#1520,#1521,#1529,#1537,#1543));
#1545=FACE_BOUND('',#1544,.T.);
#1546=ADVANCED_FACE('F806',(#1545),#1519,.T.);
#1547=CARTESIAN_POINT('',(32.05,15.5,11.5));
#1548=DIRECTION('',(-1.,0.,0.));
#1549=DIRECTION('',(0.,-1.,0.));
#1550=AXIS2_PLACEMENT_3D('',#1547,#1548,#1549);
#1551=CYLINDRICAL_SURFACE('',#1550,5.);
#1552=CARTESIAN_POINT('',(32.05,15.5,11.5));
#1553=DIRECTION('',(-1.,0.,0.));
#1554=DIRECTION('',(0.,-1.,0.));
#1555=AXIS2_PLACEMENT_3D('',#1552,#1553,#1554);
#1556=CIRCLE('',#1555,5.);
#1557=EDGE_CURVE('E356',#1476,#1535,#1556,.F.);
#1558=ORIENTED_EDGE('',*,*,#1557,.T.);
#1559=ORIENTED_EDGE('',*,*,#1536,.T.);
#1560=CARTESIAN_POINT('',(39.35,15.5,11.5));
#1561=DIRECTION('',(-1.,0.,0.));
#1562=DIRECTION('',(0.,-1.,0.));
#1563=AXIS2_PLACEMENT_3D('',#1560,#1561,#1562);
#1564=CIRCLE('',#1563,5.);
#1565=EDGE_CURVE('E355',#1484,#1527,#1564,.F.);
#1566=ORIENTED_EDGE('',*,*,#1565,.F.);
#1567=ORIENTED_EDGE('',*,*,#1485,.F.);
#1568=EDGE_LOOP('',(#1558,#1559,#1566,#1567));
#1569=FACE_BOUND('',#1568,.T.);
#1570=ADVANCED_FACE('F852',(#1569),#1551,.T.);
#1571=CARTESIAN_POINT('',(39.35,15.5,0.));
#1572=DIRECTION('',(1.,0.,0.));
#1573=DIRECTION('',(0.,1.,0.));
#1574=AXIS2_PLACEMENT_3D('',#1571,#1572,#1573);
#1575=PLANE('',#1574);
#1576=ORIENTED_EDGE('',*,*,#1565,.T.);
#1577=ORIENTED_EDGE('',*,*,#1528,.T.);
#1578=ORIENTED_EDGE('',*,*,#1509,.F.);
#1579=ORIENTED_EDGE('',*,*,#1491,.F.);
#1580=EDGE_LOOP('',(#1576,#1577,#1578,#1579));
#1581=FACE_BOUND('',#1580,.T.);
#1582=CARTESIAN_POINT('',(39.35,15.5,11.5));
#1583=DIRECTION('',(1.,0.,0.));
#1584=DIRECTION('',(0.,0.,-1.));
#1585=AXIS2_PLACEMENT_3D('',#1582,#1583,#1584);
#1586=CIRCLE('',#1585,2.);
#1587=CARTESIAN_POINT('',(39.35,15.5,9.5));
#1588=VERTEX_POINT('',#1587);
#1589=EDGE_CURVE('E447',#1588,#1588,#1586,.T.);
#1590=ORIENTED_EDGE('',*,*,#1589,.F.);
#1591=EDGE_LOOP('',(#1590));
#1592=FACE_BOUND('',#1591,.T.);
#1593=ADVANCED_FACE('F848',(#1581,#1592),#1575,.T.);
#1594=CARTESIAN_POINT('',(32.05,15.5,0.));
#1595=DIRECTION('',(1.,0.,0.));
#1596=DIRECTION('',(0.,1.,0.));
#1597=AXIS2_PLACEMENT_3D('',#1594,#1595,#1596);
#1598=PLANE('',#1597);
#1599=CARTESIAN_POINT('',(32.05,15.5,11.5));
#1600=DIRECTION('',(1.,0.,0.));
#1601=DIRECTION('',(0.,0.,-1.));
#1602=AXIS2_PLACEMENT_3D('',#1599,#1600,#1601);
#1603=CIRCLE('',#1602,2.);
#1604=CARTESIAN_POINT('',(32.05,15.5,9.5));
#1605=VERTEX_POINT('',#1604);
#1606=EDGE_CURVE('E1361',#1605,#1605,#1603,.T.);
#1607=ORIENTED_EDGE('',*,*,#1606,.T.);
#1608=EDGE_LOOP('',(#1607));
#1609=FACE_BOUND('',#1608,.T.);
#1610=ORIENTED_EDGE('',*,*,#1542,.F.);
#1611=ORIENTED_EDGE('',*,*,#1557,.F.);
#1612=ORIENTED_EDGE('',*,*,#1477,.F.);
#1613=ORIENTED_EDGE('',*,*,#1460,.F.);
#1614=EDGE_LOOP('',(#1610,#1611,#1612,#1613));
#1615=FACE_BOUND('',#1614,.T.);
#1616=ADVANCED_FACE('F851',(#1609,#1615),#1598,.F.);
#1617=CARTESIAN_POINT('',(15.35,5.5926726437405,11.5));
#1618=DIRECTION('',(0.,-0.504676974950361,0.863308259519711));
#1619=DIRECTION('',(0.,-0.863308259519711,-0.504676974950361));
#1620=AXIS2_PLACEMENT_3D('',#1617,#1618,#1619);
#1621=PLANE('',#1620);
#1622=DIRECTION('',(0.,-0.863308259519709,-0.504676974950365));
#1623=VECTOR('',#1622,1.);
#1624=CARTESIAN_POINT('',(15.35,12.9766151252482,15.8165412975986));
#1625=LINE('',#1624,#1623);
#1626=CARTESIAN_POINT('',(15.35,12.9766151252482,15.8165412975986));
#1627=VERTEX_POINT('',#1626);
#1628=EDGE_CURVE('E610',#1627,#1306,#1625,.T.);
#1629=ORIENTED_EDGE('',*,*,#1628,.T.);
#1630=ORIENTED_EDGE('',*,*,#1307,.T.);
#1631=DIRECTION('',(0.,-0.863308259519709,-0.504676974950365));
#1632=VECTOR('',#1631,1.);
#1633=CARTESIAN_POINT('',(23.5,12.9766151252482,15.8165412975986));
#1634=LINE('',#1633,#1632);
#1635=CARTESIAN_POINT('',(23.5,12.9766151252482,15.8165412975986));
#1636=VERTEX_POINT('',#1635);
#1637=EDGE_CURVE('E607',#1636,#1298,#1634,.T.);
#1638=ORIENTED_EDGE('',*,*,#1637,.F.);
#1639=DIRECTION('',(-1.,0.,0.));
#1640=VECTOR('',#1639,1.);
#1641=CARTESIAN_POINT('',(15.35,12.9766151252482,15.8165412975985));
#1642=LINE('',#1641,#1640);
#1643=EDGE_CURVE('E361',#1627,#1636,#1642,.F.);
#1644=ORIENTED_EDGE('',*,*,#1643,.F.);
#1645=EDGE_LOOP('',(#1629,#1630,#1638,#1644));
#1646=FACE_BOUND('',#1645,.T.);
#1647=ADVANCED_FACE('F859',(#1646),#1621,.T.);
#1648=CARTESIAN_POINT('',(15.35,15.5,11.5));
#1649=DIRECTION('',(-1.,0.,0.));
#1650=DIRECTION('',(0.,-1.,0.));
#1651=AXIS2_PLACEMENT_3D('',#1648,#1649,#1650);
#1652=CYLINDRICAL_SURFACE('',#1651,5.);
#1653=CARTESIAN_POINT('',(15.35,15.5,11.5));
#1654=DIRECTION('',(-1.,0.,0.));
#1655=DIRECTION('',(0.,-1.,0.));
#1656=AXIS2_PLACEMENT_3D('',#1653,#1654,#1655);
#1657=CIRCLE('',#1656,5.);
#1658=EDGE_CURVE('E364',#1421,#1627,#1657,.F.);
#1659=ORIENTED_EDGE('',*,*,#1658,.T.);
#1660=ORIENTED_EDGE('',*,*,#1643,.T.);
#1661=CARTESIAN_POINT('',(23.5,15.5,11.5));
#1662=DIRECTION('',(-1.,0.,0.));
#1663=DIRECTION('',(0.,-1.,0.));
#1664=AXIS2_PLACEMENT_3D('',#1661,#1662,#1663);
#1665=CIRCLE('',#1664,5.);
#1666=EDGE_CURVE('E363',#1429,#1636,#1665,.F.);
#1667=ORIENTED_EDGE('',*,*,#1666,.F.);
#1668=ORIENTED_EDGE('',*,*,#1430,.F.);
#1669=EDGE_LOOP('',(#1659,#1660,#1667,#1668));
#1670=FACE_BOUND('',#1669,.T.);
#1671=ADVANCED_FACE('F867',(#1670),#1652,.T.);
#1672=CARTESIAN_POINT('',(23.5,15.5,0.));
#1673=DIRECTION('',(1.,0.,0.));
#1674=DIRECTION('',(0.,1.,0.));
#1675=AXIS2_PLACEMENT_3D('',#1672,#1673,#1674);
#1676=PLANE('',#1675);
#1677=ORIENTED_EDGE('',*,*,#1666,.T.);
#1678=ORIENTED_EDGE('',*,*,#1637,.T.);
#1679=ORIENTED_EDGE('',*,*,#1452,.F.);
#1680=ORIENTED_EDGE('',*,*,#1436,.F.);
#1681=EDGE_LOOP('',(#1677,#1678,#1679,#1680));
#1682=FACE_BOUND('',#1681,.T.);
#1683=CARTESIAN_POINT('',(23.5,15.5,11.5));
#1684=DIRECTION('',(1.,0.,0.));
#1685=DIRECTION('',(0.,0.,-1.));
#1686=AXIS2_PLACEMENT_3D('',#1683,#1684,#1685);
#1687=CIRCLE('',#1686,2.);
#1688=CARTESIAN_POINT('',(23.5,15.5,9.5));
#1689=VERTEX_POINT('',#1688);
#1690=EDGE_CURVE('E1358',#1689,#1689,#1687,.T.);
#1691=ORIENTED_EDGE('',*,*,#1690,.F.);
#1692=EDGE_LOOP('',(#1691));
#1693=FACE_BOUND('',#1692,.T.);
#1694=ADVANCED_FACE('F863',(#1682,#1693),#1676,.T.);
#1695=CARTESIAN_POINT('',(15.35,15.5,0.));
#1696=DIRECTION('',(1.,0.,0.));
#1697=DIRECTION('',(0.,1.,0.));
#1698=AXIS2_PLACEMENT_3D('',#1695,#1696,#1697);
#1699=PLANE('',#1698);
#1700=CARTESIAN_POINT('',(15.35,15.5,11.5));
#1701=DIRECTION('',(1.,0.,0.));
#1702=DIRECTION('',(0.,0.,-1.));
#1703=AXIS2_PLACEMENT_3D('',#1700,#1701,#1702);
#1704=CIRCLE('',#1703,2.);
#1705=CARTESIAN_POINT('',(15.35,15.5,9.5));
#1706=VERTEX_POINT('',#1705);
#1707=EDGE_CURVE('E1353',#1706,#1706,#1704,.T.);
#1708=ORIENTED_EDGE('',*,*,#1707,.T.);
#1709=EDGE_LOOP('',(#1708));
#1710=FACE_BOUND('',#1709,.T.);
#1711=ORIENTED_EDGE('',*,*,#1628,.F.);
#1712=ORIENTED_EDGE('',*,*,#1658,.F.);
#1713=ORIENTED_EDGE('',*,*,#1422,.F.);
#1714=ORIENTED_EDGE('',*,*,#1397,.F.);
#1715=EDGE_LOOP('',(#1711,#1712,#1713,#1714));
#1716=FACE_BOUND('',#1715,.T.);
#1717=ADVANCED_FACE('F866',(#1710,#1716),#1699,.F.);
#1718=CARTESIAN_POINT('',(6.8,12.9766151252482,15.8165412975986));
#1719=DIRECTION('',(0.,-0.504676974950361,0.863308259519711));
#1720=DIRECTION('',(0.,-0.863308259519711,-0.504676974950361));
#1721=AXIS2_PLACEMENT_3D('',#1718,#1719,#1720);
#1722=PLANE('',#1721);
#1723=DIRECTION('',(0.,-0.863308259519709,-0.504676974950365));
#1724=VECTOR('',#1723,1.);
#1725=CARTESIAN_POINT('',(6.8,12.9766151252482,15.8165412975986));
#1726=LINE('',#1725,#1724);
#1727=CARTESIAN_POINT('',(6.8,12.9766151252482,15.8165412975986));
#1728=VERTEX_POINT('',#1727);
#1729=EDGE_CURVE('E613',#1728,#1314,#1726,.T.);
#1730=ORIENTED_EDGE('',*,*,#1729,.F.);
#1731=DIRECTION('',(1.,0.,0.));
#1732=VECTOR('',#1731,1.);
#1733=CARTESIAN_POINT('',(6.8,12.9766151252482,15.8165412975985));
#1734=LINE('',#1733,#1732);
#1735=CARTESIAN_POINT('',(-1.35,12.9766151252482,15.8165412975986));
#1736=VERTEX_POINT('',#1735);
#1737=EDGE_CURVE('E365',#1736,#1728,#1734,.T.);
#1738=ORIENTED_EDGE('',*,*,#1737,.F.);
#1739=DIRECTION('',(0.,-0.863308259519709,-0.504676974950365));
#1740=VECTOR('',#1739,1.);
#1741=CARTESIAN_POINT('',(-1.35,12.9766151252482,15.8165412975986));
#1742=LINE('',#1741,#1740);
#1743=EDGE_CURVE('E616',#1736,#1322,#1742,.T.);
#1744=ORIENTED_EDGE('',*,*,#1743,.T.);
#1745=ORIENTED_EDGE('',*,*,#1323,.T.);
#1746=EDGE_LOOP('',(#1730,#1738,#1744,#1745));
#1747=FACE_BOUND('',#1746,.T.);
#1748=ADVANCED_FACE('F874',(#1747),#1722,.T.);
#1749=CARTESIAN_POINT('',(6.8,15.5,11.5));
#1750=DIRECTION('',(1.,0.,0.));
#1751=DIRECTION('',(0.,1.,0.));
#1752=AXIS2_PLACEMENT_3D('',#1749,#1750,#1751);
#1753=CYLINDRICAL_SURFACE('',#1752,5.);
#1754=CARTESIAN_POINT('',(6.8,15.5,11.5));
#1755=DIRECTION('',(1.,0.,0.));
#1756=DIRECTION('',(0.,1.,0.));
#1757=AXIS2_PLACEMENT_3D('',#1754,#1755,#1756);
#1758=CIRCLE('',#1757,5.);
#1759=EDGE_CURVE('E366',#1366,#1728,#1758,.T.);
#1760=ORIENTED_EDGE('',*,*,#1759,.F.);
#1761=ORIENTED_EDGE('',*,*,#1382,.F.);
#1762=CARTESIAN_POINT('',(-1.35,15.5,11.5));
#1763=DIRECTION('',(1.,0.,0.));
#1764=DIRECTION('',(0.,1.,0.));
#1765=AXIS2_PLACEMENT_3D('',#1762,#1763,#1764);
#1766=CIRCLE('',#1765,5.);
#1767=EDGE_CURVE('E367',#1375,#1736,#1766,.T.);
#1768=ORIENTED_EDGE('',*,*,#1767,.T.);
#1769=ORIENTED_EDGE('',*,*,#1737,.T.);
#1770=EDGE_LOOP('',(#1760,#1761,#1768,#1769));
#1771=FACE_BOUND('',#1770,.T.);
#1772=ADVANCED_FACE('F880',(#1771),#1753,.T.);
#1773=CARTESIAN_POINT('',(6.8,15.5,0.));
#1774=DIRECTION('',(1.,0.,0.));
#1775=DIRECTION('',(0.,1.,0.));
#1776=AXIS2_PLACEMENT_3D('',#1773,#1774,#1775);
#1777=PLANE('',#1776);
#1778=CARTESIAN_POINT('',(6.8,15.5,11.5));
#1779=DIRECTION('',(1.,0.,0.));
#1780=DIRECTION('',(0.,0.,-1.));
#1781=AXIS2_PLACEMENT_3D('',#1778,#1779,#1780);
#1782=CIRCLE('',#1781,2.);
#1783=CARTESIAN_POINT('',(6.8,15.5,9.5));
#1784=VERTEX_POINT('',#1783);
#1785=EDGE_CURVE('E1347',#1784,#1784,#1782,.T.);
#1786=ORIENTED_EDGE('',*,*,#1785,.F.);
#1787=EDGE_LOOP('',(#1786));
#1788=FACE_BOUND('',#1787,.T.);
#1789=ORIENTED_EDGE('',*,*,#1759,.T.);
#1790=ORIENTED_EDGE('',*,*,#1729,.T.);
#1791=ORIENTED_EDGE('',*,*,#1405,.F.);
#1792=ORIENTED_EDGE('',*,*,#1367,.F.);
#1793=EDGE_LOOP('',(#1789,#1790,#1791,#1792));
#1794=FACE_BOUND('',#1793,.T.);
#1795=ADVANCED_FACE('F876',(#1788,#1794),#1777,.T.);
#1796=CARTESIAN_POINT('',(-1.35,15.5,0.));
#1797=DIRECTION('',(1.,0.,0.));
#1798=DIRECTION('',(0.,1.,0.));
#1799=AXIS2_PLACEMENT_3D('',#1796,#1797,#1798);
#1800=PLANE('',#1799);
#1801=ORIENTED_EDGE('',*,*,#1743,.F.);
#1802=ORIENTED_EDGE('',*,*,#1767,.F.);
#1803=ORIENTED_EDGE('',*,*,#1376,.F.);
#1804=ORIENTED_EDGE('',*,*,#1349,.F.);
#1805=EDGE_LOOP('',(#1801,#1802,#1803,#1804));
#1806=FACE_BOUND('',#1805,.T.);
#1807=CARTESIAN_POINT('',(-1.35,15.5,11.5));
#1808=DIRECTION('',(1.,0.,0.));
#1809=DIRECTION('',(0.,0.,-1.));
#1810=AXIS2_PLACEMENT_3D('',#1807,#1808,#1809);
#1811=CIRCLE('',#1810,2.);
#1812=CARTESIAN_POINT('',(-1.35,15.5,9.5));
#1813=VERTEX_POINT('',#1812);
#1814=EDGE_CURVE('E1350',#1813,#1813,#1811,.T.);
#1815=ORIENTED_EDGE('',*,*,#1814,.T.);
#1816=EDGE_LOOP('',(#1815));
#1817=FACE_BOUND('',#1816,.T.);
#1818=ADVANCED_FACE('F879',(#1806,#1817),#1800,.F.);
#1819=CARTESIAN_POINT('',(-9.50010307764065,15.5,11.5));
#1820=DIRECTION('',(1.,0.,0.));
#1821=DIRECTION('',(0.,1.,0.));
#1822=AXIS2_PLACEMENT_3D('',#1819,#1820,#1821);
#1823=CYLINDRICAL_SURFACE('',#1822,2.);
#1824=ORIENTED_EDGE('',*,*,#1785,.T.);
#1825=EDGE_LOOP('',(#1824));
#1826=FACE_BOUND('',#1825,.T.);
#1827=ORIENTED_EDGE('',*,*,#1814,.F.);
#1828=EDGE_LOOP('',(#1827));
#1829=FACE_BOUND('',#1828,.T.);
#1830=ADVANCED_FACE('F887',(#1826,#1829),#1823,.F.);
#1831=ORIENTED_EDGE('',*,*,#1690,.T.);
#1832=EDGE_LOOP('',(#1831));
#1833=FACE_BOUND('',#1832,.T.);
#1834=ORIENTED_EDGE('',*,*,#1707,.F.);
#1835=EDGE_LOOP('',(#1834));
#1836=FACE_BOUND('',#1835,.T.);
#1837=ADVANCED_FACE('F1327',(#1833,#1836),#1823,.F.);
#1838=ORIENTED_EDGE('',*,*,#1589,.T.);
#1839=EDGE_LOOP('',(#1838));
#1840=FACE_BOUND('',#1839,.T.);
#1841=ORIENTED_EDGE('',*,*,#1606,.F.);
#1842=EDGE_LOOP('',(#1841));
#1843=FACE_BOUND('',#1842,.T.);
#1844=ADVANCED_FACE('F772',(#1840,#1843),#1823,.F.);
#1845=CLOSED_SHELL('',(#60,#107,#149,#196,#227,#251,#276,#300,#325,#342,#373,#397,#422,#446,
#471,#488,#513,#538,#558,#578,#620,#662,#704,#746,#792,#823,#882,#915,#948,#972,#998,#1031,
#1055,#1081,#1098,#1133,#1150,#1222,#1250,#1275,#1336,#1355,#1386,#1410,#1441,#1465,#1496,#1514,
#1546,#1570,#1593,#1616,#1647,#1671,#1694,#1717,#1748,#1772,#1795,#1818,#1830,#1837,#1844));
#1846=MANIFOLD_SOLID_BREP('B1',#1845);
#1847=ADVANCED_BREP_SHAPE_REPRESENTATION('',(#18,#1846),#14);
#1848=SHAPE_DEFINITION_REPRESENTATION(#9,#1847);
ENDSEC;
END-ISO-10303-21;
